VERSION 5.8 ;
BUSBITCHARS "[]" ;
DIVIDERCHAR "/" ;
UNITS
    DATABASE MICRONS 1000 ;
END UNITS

VIA ino_decode_queue_via1_2_1000_440_1_2_410_410
  VIARULE via1Array ;
  CUTSIZE 0.19 0.19 ;
  LAYERS Metal1 Via1 Metal2 ;
  CUTSPACING 0.22 0.22 ;
  ENCLOSURE 0.05 0.125 0.005 0.05 ;
  ROWCOL 1 2 ;
END ino_decode_queue_via1_2_1000_440_1_2_410_410

VIA ino_decode_queue_via2_3_1000_440_1_2_410_410
  VIARULE via2Array ;
  CUTSIZE 0.19 0.19 ;
  LAYERS Metal2 Via2 Metal3 ;
  CUTSPACING 0.22 0.22 ;
  ENCLOSURE 0.005 0.05 0.05 0.005 ;
  ROWCOL 1 2 ;
END ino_decode_queue_via2_3_1000_440_1_2_410_410

VIA ino_decode_queue_via3_4_1000_440_1_2_410_410
  VIARULE via3Array ;
  CUTSIZE 0.19 0.19 ;
  LAYERS Metal3 Via3 Metal4 ;
  CUTSPACING 0.22 0.22 ;
  ENCLOSURE 0.05 0.005 0.2 0.05 ;
  ROWCOL 1 2 ;
END ino_decode_queue_via3_4_1000_440_1_2_410_410

VIA ino_decode_queue_via4_5_1000_2000_1_1_840_840
  VIARULE viaTop1Array ;
  CUTSIZE 0.42 0.42 ;
  LAYERS Metal4 TopVia1 TopMetal1 ;
  CUTSPACING 0.42 0.42 ;
  ENCLOSURE 0.29 0.1 0.42 0.79 ;
END ino_decode_queue_via4_5_1000_2000_1_1_840_840

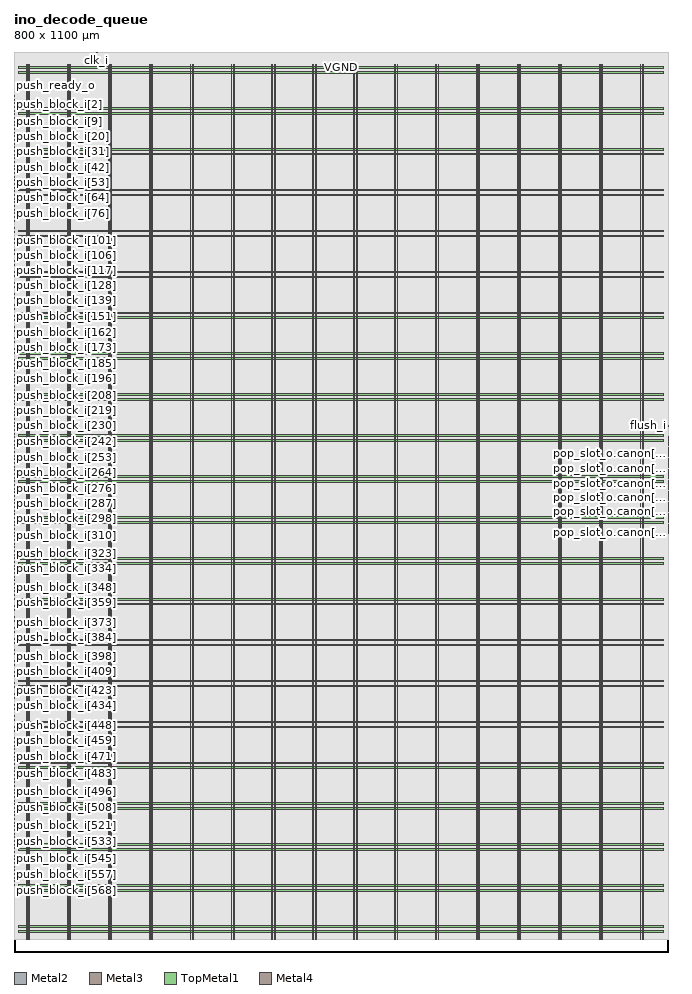
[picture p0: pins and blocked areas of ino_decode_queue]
MACRO ino_decode_queue
  FOREIGN ino_decode_queue 0 0 ;
  CLASS BLOCK ;
  SIZE 800 BY 1100 ;
  PIN clk_i
    DIRECTION INPUT ;
    USE SIGNAL ;
    PORT
      LAYER Metal2 ;
        RECT  101.08 1099.6 101.48 1100 ;
    END
  END clk_i
  PIN flush_i
    DIRECTION INPUT ;
    USE SIGNAL ;
    PORT
      LAYER Metal3 ;
        RECT  799.6 642.82 800 643.22 ;
    END
  END flush_i
  PIN pop_slot_o.canon[0]
    DIRECTION OUTPUT ;
    USE SIGNAL ;
    PORT
      LAYER Metal3 ;
        RECT  799.6 512.62 800 513.02 ;
    END
  END pop_slot_o.canon[0]
  PIN pop_slot_o.canon[10]
    DIRECTION OUTPUT ;
    USE SIGNAL ;
    PORT
      LAYER Metal3 ;
        RECT  799.6 537.82 800 538.22 ;
    END
  END pop_slot_o.canon[10]
  PIN pop_slot_o.canon[11]
    DIRECTION OUTPUT ;
    USE SIGNAL ;
    PORT
      LAYER Metal3 ;
        RECT  799.6 540.34 800 540.74 ;
    END
  END pop_slot_o.canon[11]
  PIN pop_slot_o.canon[12]
    DIRECTION OUTPUT ;
    USE SIGNAL ;
    PORT
      LAYER Metal3 ;
        RECT  799.6 542.86 800 543.26 ;
    END
  END pop_slot_o.canon[12]
  PIN pop_slot_o.canon[13]
    DIRECTION OUTPUT ;
    USE SIGNAL ;
    PORT
      LAYER Metal3 ;
        RECT  799.6 545.38 800 545.78 ;
    END
  END pop_slot_o.canon[13]
  PIN pop_slot_o.canon[14]
    DIRECTION OUTPUT ;
    USE SIGNAL ;
    PORT
      LAYER Metal3 ;
        RECT  799.6 547.9 800 548.3 ;
    END
  END pop_slot_o.canon[14]
  PIN pop_slot_o.canon[15]
    DIRECTION OUTPUT ;
    USE SIGNAL ;
    PORT
      LAYER Metal3 ;
        RECT  799.6 550.42 800 550.82 ;
    END
  END pop_slot_o.canon[15]
  PIN pop_slot_o.canon[16]
    DIRECTION OUTPUT ;
    USE SIGNAL ;
    PORT
      LAYER Metal3 ;
        RECT  799.6 552.94 800 553.34 ;
    END
  END pop_slot_o.canon[16]
  PIN pop_slot_o.canon[17]
    DIRECTION OUTPUT ;
    USE SIGNAL ;
    PORT
      LAYER Metal3 ;
        RECT  799.6 555.46 800 555.86 ;
    END
  END pop_slot_o.canon[17]
  PIN pop_slot_o.canon[18]
    DIRECTION OUTPUT ;
    USE SIGNAL ;
    PORT
      LAYER Metal3 ;
        RECT  799.6 557.98 800 558.38 ;
    END
  END pop_slot_o.canon[18]
  PIN pop_slot_o.canon[19]
    DIRECTION OUTPUT ;
    USE SIGNAL ;
    PORT
      LAYER Metal3 ;
        RECT  799.6 560.5 800 560.9 ;
    END
  END pop_slot_o.canon[19]
  PIN pop_slot_o.canon[1]
    DIRECTION OUTPUT ;
    USE SIGNAL ;
    PORT
      LAYER Metal3 ;
        RECT  799.6 515.14 800 515.54 ;
    END
  END pop_slot_o.canon[1]
  PIN pop_slot_o.canon[20]
    DIRECTION OUTPUT ;
    USE SIGNAL ;
    PORT
      LAYER Metal3 ;
        RECT  799.6 563.02 800 563.42 ;
    END
  END pop_slot_o.canon[20]
  PIN pop_slot_o.canon[21]
    DIRECTION OUTPUT ;
    USE SIGNAL ;
    PORT
      LAYER Metal3 ;
        RECT  799.6 565.54 800 565.94 ;
    END
  END pop_slot_o.canon[21]
  PIN pop_slot_o.canon[22]
    DIRECTION OUTPUT ;
    USE SIGNAL ;
    PORT
      LAYER Metal3 ;
        RECT  799.6 568.06 800 568.46 ;
    END
  END pop_slot_o.canon[22]
  PIN pop_slot_o.canon[23]
    DIRECTION OUTPUT ;
    USE SIGNAL ;
    PORT
      LAYER Metal3 ;
        RECT  799.6 570.58 800 570.98 ;
    END
  END pop_slot_o.canon[23]
  PIN pop_slot_o.canon[24]
    DIRECTION OUTPUT ;
    USE SIGNAL ;
    PORT
      LAYER Metal3 ;
        RECT  799.6 573.1 800 573.5 ;
    END
  END pop_slot_o.canon[24]
  PIN pop_slot_o.canon[25]
    DIRECTION OUTPUT ;
    USE SIGNAL ;
    PORT
      LAYER Metal3 ;
        RECT  799.6 575.62 800 576.02 ;
    END
  END pop_slot_o.canon[25]
  PIN pop_slot_o.canon[26]
    DIRECTION OUTPUT ;
    USE SIGNAL ;
    PORT
      LAYER Metal3 ;
        RECT  799.6 578.14 800 578.54 ;
    END
  END pop_slot_o.canon[26]
  PIN pop_slot_o.canon[27]
    DIRECTION OUTPUT ;
    USE SIGNAL ;
    PORT
      LAYER Metal3 ;
        RECT  799.6 580.66 800 581.06 ;
    END
  END pop_slot_o.canon[27]
  PIN pop_slot_o.canon[28]
    DIRECTION OUTPUT ;
    USE SIGNAL ;
    PORT
      LAYER Metal3 ;
        RECT  799.6 583.18 800 583.58 ;
    END
  END pop_slot_o.canon[28]
  PIN pop_slot_o.canon[29]
    DIRECTION OUTPUT ;
    USE SIGNAL ;
    PORT
      LAYER Metal3 ;
        RECT  799.6 585.7 800 586.1 ;
    END
  END pop_slot_o.canon[29]
  PIN pop_slot_o.canon[2]
    DIRECTION OUTPUT ;
    USE SIGNAL ;
    PORT
      LAYER Metal3 ;
        RECT  799.6 517.66 800 518.06 ;
    END
  END pop_slot_o.canon[2]
  PIN pop_slot_o.canon[30]
    DIRECTION OUTPUT ;
    USE SIGNAL ;
    PORT
      LAYER Metal3 ;
        RECT  799.6 588.22 800 588.62 ;
    END
  END pop_slot_o.canon[30]
  PIN pop_slot_o.canon[31]
    DIRECTION OUTPUT ;
    USE SIGNAL ;
    PORT
      LAYER Metal3 ;
        RECT  799.6 590.74 800 591.14 ;
    END
  END pop_slot_o.canon[31]
  PIN pop_slot_o.canon[32]
    DIRECTION OUTPUT ;
    USE SIGNAL ;
    PORT
      LAYER Metal3 ;
        RECT  799.6 593.26 800 593.66 ;
    END
  END pop_slot_o.canon[32]
  PIN pop_slot_o.canon[33]
    DIRECTION OUTPUT ;
    USE SIGNAL ;
    PORT
      LAYER Metal3 ;
        RECT  799.6 594.94 800 595.34 ;
    END
  END pop_slot_o.canon[33]
  PIN pop_slot_o.canon[34]
    DIRECTION OUTPUT ;
    USE SIGNAL ;
    PORT
      LAYER Metal3 ;
        RECT  799.6 596.62 800 597.02 ;
    END
  END pop_slot_o.canon[34]
  PIN pop_slot_o.canon[35]
    DIRECTION OUTPUT ;
    USE SIGNAL ;
    PORT
      LAYER Metal3 ;
        RECT  799.6 598.3 800 598.7 ;
    END
  END pop_slot_o.canon[35]
  PIN pop_slot_o.canon[36]
    DIRECTION OUTPUT ;
    USE SIGNAL ;
    PORT
      LAYER Metal3 ;
        RECT  799.6 599.98 800 600.38 ;
    END
  END pop_slot_o.canon[36]
  PIN pop_slot_o.canon[37]
    DIRECTION OUTPUT ;
    USE SIGNAL ;
    PORT
      LAYER Metal3 ;
        RECT  799.6 601.66 800 602.06 ;
    END
  END pop_slot_o.canon[37]
  PIN pop_slot_o.canon[38]
    DIRECTION OUTPUT ;
    USE SIGNAL ;
    PORT
      LAYER Metal3 ;
        RECT  799.6 603.34 800 603.74 ;
    END
  END pop_slot_o.canon[38]
  PIN pop_slot_o.canon[39]
    DIRECTION OUTPUT ;
    USE SIGNAL ;
    PORT
      LAYER Metal3 ;
        RECT  799.6 605.02 800 605.42 ;
    END
  END pop_slot_o.canon[39]
  PIN pop_slot_o.canon[3]
    DIRECTION OUTPUT ;
    USE SIGNAL ;
    PORT
      LAYER Metal3 ;
        RECT  799.6 520.18 800 520.58 ;
    END
  END pop_slot_o.canon[3]
  PIN pop_slot_o.canon[40]
    DIRECTION OUTPUT ;
    USE SIGNAL ;
    PORT
      LAYER Metal3 ;
        RECT  799.6 606.7 800 607.1 ;
    END
  END pop_slot_o.canon[40]
  PIN pop_slot_o.canon[41]
    DIRECTION OUTPUT ;
    USE SIGNAL ;
    PORT
      LAYER Metal3 ;
        RECT  799.6 608.38 800 608.78 ;
    END
  END pop_slot_o.canon[41]
  PIN pop_slot_o.canon[42]
    DIRECTION OUTPUT ;
    USE SIGNAL ;
    PORT
      LAYER Metal3 ;
        RECT  799.6 610.06 800 610.46 ;
    END
  END pop_slot_o.canon[42]
  PIN pop_slot_o.canon[43]
    DIRECTION OUTPUT ;
    USE SIGNAL ;
    PORT
      LAYER Metal3 ;
        RECT  799.6 611.74 800 612.14 ;
    END
  END pop_slot_o.canon[43]
  PIN pop_slot_o.canon[44]
    DIRECTION OUTPUT ;
    USE SIGNAL ;
    PORT
      LAYER Metal3 ;
        RECT  799.6 613.42 800 613.82 ;
    END
  END pop_slot_o.canon[44]
  PIN pop_slot_o.canon[45]
    DIRECTION OUTPUT ;
    USE SIGNAL ;
    PORT
      LAYER Metal3 ;
        RECT  799.6 615.1 800 615.5 ;
    END
  END pop_slot_o.canon[45]
  PIN pop_slot_o.canon[46]
    DIRECTION OUTPUT ;
    USE SIGNAL ;
    PORT
      LAYER Metal3 ;
        RECT  799.6 616.78 800 617.18 ;
    END
  END pop_slot_o.canon[46]
  PIN pop_slot_o.canon[47]
    DIRECTION OUTPUT ;
    USE SIGNAL ;
    PORT
      LAYER Metal3 ;
        RECT  799.6 618.46 800 618.86 ;
    END
  END pop_slot_o.canon[47]
  PIN pop_slot_o.canon[48]
    DIRECTION OUTPUT ;
    USE SIGNAL ;
    PORT
      LAYER Metal3 ;
        RECT  799.6 620.14 800 620.54 ;
    END
  END pop_slot_o.canon[48]
  PIN pop_slot_o.canon[49]
    DIRECTION OUTPUT ;
    USE SIGNAL ;
    PORT
      LAYER Metal3 ;
        RECT  799.6 621.82 800 622.22 ;
    END
  END pop_slot_o.canon[49]
  PIN pop_slot_o.canon[4]
    DIRECTION OUTPUT ;
    USE SIGNAL ;
    PORT
      LAYER Metal3 ;
        RECT  799.6 522.7 800 523.1 ;
    END
  END pop_slot_o.canon[4]
  PIN pop_slot_o.canon[50]
    DIRECTION OUTPUT ;
    USE SIGNAL ;
    PORT
      LAYER Metal3 ;
        RECT  799.6 623.5 800 623.9 ;
    END
  END pop_slot_o.canon[50]
  PIN pop_slot_o.canon[51]
    DIRECTION OUTPUT ;
    USE SIGNAL ;
    PORT
      LAYER Metal3 ;
        RECT  799.6 625.18 800 625.58 ;
    END
  END pop_slot_o.canon[51]
  PIN pop_slot_o.canon[52]
    DIRECTION OUTPUT ;
    USE SIGNAL ;
    PORT
      LAYER Metal3 ;
        RECT  799.6 626.86 800 627.26 ;
    END
  END pop_slot_o.canon[52]
  PIN pop_slot_o.canon[53]
    DIRECTION OUTPUT ;
    USE SIGNAL ;
    PORT
      LAYER Metal3 ;
        RECT  799.6 628.54 800 628.94 ;
    END
  END pop_slot_o.canon[53]
  PIN pop_slot_o.canon[54]
    DIRECTION OUTPUT ;
    USE SIGNAL ;
    PORT
      LAYER Metal3 ;
        RECT  799.6 630.22 800 630.62 ;
    END
  END pop_slot_o.canon[54]
  PIN pop_slot_o.canon[55]
    DIRECTION OUTPUT ;
    USE SIGNAL ;
    PORT
      LAYER Metal3 ;
        RECT  799.6 631.06 800 631.46 ;
    END
  END pop_slot_o.canon[55]
  PIN pop_slot_o.canon[5]
    DIRECTION OUTPUT ;
    USE SIGNAL ;
    PORT
      LAYER Metal3 ;
        RECT  799.6 525.22 800 525.62 ;
    END
  END pop_slot_o.canon[5]
  PIN pop_slot_o.canon[6]
    DIRECTION OUTPUT ;
    USE SIGNAL ;
    PORT
      LAYER Metal3 ;
        RECT  799.6 527.74 800 528.14 ;
    END
  END pop_slot_o.canon[6]
  PIN pop_slot_o.canon[7]
    DIRECTION OUTPUT ;
    USE SIGNAL ;
    PORT
      LAYER Metal3 ;
        RECT  799.6 530.26 800 530.66 ;
    END
  END pop_slot_o.canon[7]
  PIN pop_slot_o.canon[8]
    DIRECTION OUTPUT ;
    USE SIGNAL ;
    PORT
      LAYER Metal3 ;
        RECT  799.6 532.78 800 533.18 ;
    END
  END pop_slot_o.canon[8]
  PIN pop_slot_o.canon[9]
    DIRECTION OUTPUT ;
    USE SIGNAL ;
    PORT
      LAYER Metal3 ;
        RECT  799.6 535.3 800 535.7 ;
    END
  END pop_slot_o.canon[9]
  PIN pop_slot_o.pc[0]
    DIRECTION OUTPUT ;
    USE SIGNAL ;
    PORT
      LAYER Metal3 ;
        RECT  799.6 513.46 800 513.86 ;
    END
  END pop_slot_o.pc[0]
  PIN pop_slot_o.pc[10]
    DIRECTION OUTPUT ;
    USE SIGNAL ;
    PORT
      LAYER Metal3 ;
        RECT  799.6 538.66 800 539.06 ;
    END
  END pop_slot_o.pc[10]
  PIN pop_slot_o.pc[11]
    DIRECTION OUTPUT ;
    USE SIGNAL ;
    PORT
      LAYER Metal3 ;
        RECT  799.6 541.18 800 541.58 ;
    END
  END pop_slot_o.pc[11]
  PIN pop_slot_o.pc[12]
    DIRECTION OUTPUT ;
    USE SIGNAL ;
    PORT
      LAYER Metal3 ;
        RECT  799.6 543.7 800 544.1 ;
    END
  END pop_slot_o.pc[12]
  PIN pop_slot_o.pc[13]
    DIRECTION OUTPUT ;
    USE SIGNAL ;
    PORT
      LAYER Metal3 ;
        RECT  799.6 546.22 800 546.62 ;
    END
  END pop_slot_o.pc[13]
  PIN pop_slot_o.pc[14]
    DIRECTION OUTPUT ;
    USE SIGNAL ;
    PORT
      LAYER Metal3 ;
        RECT  799.6 548.74 800 549.14 ;
    END
  END pop_slot_o.pc[14]
  PIN pop_slot_o.pc[15]
    DIRECTION OUTPUT ;
    USE SIGNAL ;
    PORT
      LAYER Metal3 ;
        RECT  799.6 551.26 800 551.66 ;
    END
  END pop_slot_o.pc[15]
  PIN pop_slot_o.pc[16]
    DIRECTION OUTPUT ;
    USE SIGNAL ;
    PORT
      LAYER Metal3 ;
        RECT  799.6 553.78 800 554.18 ;
    END
  END pop_slot_o.pc[16]
  PIN pop_slot_o.pc[17]
    DIRECTION OUTPUT ;
    USE SIGNAL ;
    PORT
      LAYER Metal3 ;
        RECT  799.6 556.3 800 556.7 ;
    END
  END pop_slot_o.pc[17]
  PIN pop_slot_o.pc[18]
    DIRECTION OUTPUT ;
    USE SIGNAL ;
    PORT
      LAYER Metal3 ;
        RECT  799.6 558.82 800 559.22 ;
    END
  END pop_slot_o.pc[18]
  PIN pop_slot_o.pc[19]
    DIRECTION OUTPUT ;
    USE SIGNAL ;
    PORT
      LAYER Metal3 ;
        RECT  799.6 561.34 800 561.74 ;
    END
  END pop_slot_o.pc[19]
  PIN pop_slot_o.pc[1]
    DIRECTION OUTPUT ;
    USE SIGNAL ;
    PORT
      LAYER Metal3 ;
        RECT  799.6 515.98 800 516.38 ;
    END
  END pop_slot_o.pc[1]
  PIN pop_slot_o.pc[20]
    DIRECTION OUTPUT ;
    USE SIGNAL ;
    PORT
      LAYER Metal3 ;
        RECT  799.6 563.86 800 564.26 ;
    END
  END pop_slot_o.pc[20]
  PIN pop_slot_o.pc[21]
    DIRECTION OUTPUT ;
    USE SIGNAL ;
    PORT
      LAYER Metal3 ;
        RECT  799.6 566.38 800 566.78 ;
    END
  END pop_slot_o.pc[21]
  PIN pop_slot_o.pc[22]
    DIRECTION OUTPUT ;
    USE SIGNAL ;
    PORT
      LAYER Metal3 ;
        RECT  799.6 568.9 800 569.3 ;
    END
  END pop_slot_o.pc[22]
  PIN pop_slot_o.pc[23]
    DIRECTION OUTPUT ;
    USE SIGNAL ;
    PORT
      LAYER Metal3 ;
        RECT  799.6 571.42 800 571.82 ;
    END
  END pop_slot_o.pc[23]
  PIN pop_slot_o.pc[24]
    DIRECTION OUTPUT ;
    USE SIGNAL ;
    PORT
      LAYER Metal3 ;
        RECT  799.6 573.94 800 574.34 ;
    END
  END pop_slot_o.pc[24]
  PIN pop_slot_o.pc[25]
    DIRECTION OUTPUT ;
    USE SIGNAL ;
    PORT
      LAYER Metal3 ;
        RECT  799.6 576.46 800 576.86 ;
    END
  END pop_slot_o.pc[25]
  PIN pop_slot_o.pc[26]
    DIRECTION OUTPUT ;
    USE SIGNAL ;
    PORT
      LAYER Metal3 ;
        RECT  799.6 578.98 800 579.38 ;
    END
  END pop_slot_o.pc[26]
  PIN pop_slot_o.pc[27]
    DIRECTION OUTPUT ;
    USE SIGNAL ;
    PORT
      LAYER Metal3 ;
        RECT  799.6 581.5 800 581.9 ;
    END
  END pop_slot_o.pc[27]
  PIN pop_slot_o.pc[28]
    DIRECTION OUTPUT ;
    USE SIGNAL ;
    PORT
      LAYER Metal3 ;
        RECT  799.6 584.02 800 584.42 ;
    END
  END pop_slot_o.pc[28]
  PIN pop_slot_o.pc[29]
    DIRECTION OUTPUT ;
    USE SIGNAL ;
    PORT
      LAYER Metal3 ;
        RECT  799.6 586.54 800 586.94 ;
    END
  END pop_slot_o.pc[29]
  PIN pop_slot_o.pc[2]
    DIRECTION OUTPUT ;
    USE SIGNAL ;
    PORT
      LAYER Metal3 ;
        RECT  799.6 518.5 800 518.9 ;
    END
  END pop_slot_o.pc[2]
  PIN pop_slot_o.pc[30]
    DIRECTION OUTPUT ;
    USE SIGNAL ;
    PORT
      LAYER Metal3 ;
        RECT  799.6 589.06 800 589.46 ;
    END
  END pop_slot_o.pc[30]
  PIN pop_slot_o.pc[31]
    DIRECTION OUTPUT ;
    USE SIGNAL ;
    PORT
      LAYER Metal3 ;
        RECT  799.6 591.58 800 591.98 ;
    END
  END pop_slot_o.pc[31]
  PIN pop_slot_o.pc[3]
    DIRECTION OUTPUT ;
    USE SIGNAL ;
    PORT
      LAYER Metal3 ;
        RECT  799.6 521.02 800 521.42 ;
    END
  END pop_slot_o.pc[3]
  PIN pop_slot_o.pc[4]
    DIRECTION OUTPUT ;
    USE SIGNAL ;
    PORT
      LAYER Metal3 ;
        RECT  799.6 523.54 800 523.94 ;
    END
  END pop_slot_o.pc[4]
  PIN pop_slot_o.pc[5]
    DIRECTION OUTPUT ;
    USE SIGNAL ;
    PORT
      LAYER Metal3 ;
        RECT  799.6 526.06 800 526.46 ;
    END
  END pop_slot_o.pc[5]
  PIN pop_slot_o.pc[6]
    DIRECTION OUTPUT ;
    USE SIGNAL ;
    PORT
      LAYER Metal3 ;
        RECT  799.6 528.58 800 528.98 ;
    END
  END pop_slot_o.pc[6]
  PIN pop_slot_o.pc[7]
    DIRECTION OUTPUT ;
    USE SIGNAL ;
    PORT
      LAYER Metal3 ;
        RECT  799.6 531.1 800 531.5 ;
    END
  END pop_slot_o.pc[7]
  PIN pop_slot_o.pc[8]
    DIRECTION OUTPUT ;
    USE SIGNAL ;
    PORT
      LAYER Metal3 ;
        RECT  799.6 533.62 800 534.02 ;
    END
  END pop_slot_o.pc[8]
  PIN pop_slot_o.pc[9]
    DIRECTION OUTPUT ;
    USE SIGNAL ;
    PORT
      LAYER Metal3 ;
        RECT  799.6 536.14 800 536.54 ;
    END
  END pop_slot_o.pc[9]
  PIN pop_slot_o.pred[0]
    DIRECTION OUTPUT ;
    USE SIGNAL ;
    PORT
      LAYER Metal3 ;
        RECT  799.6 514.3 800 514.7 ;
    END
  END pop_slot_o.pred[0]
  PIN pop_slot_o.pred[10]
    DIRECTION OUTPUT ;
    USE SIGNAL ;
    PORT
      LAYER Metal3 ;
        RECT  799.6 539.5 800 539.9 ;
    END
  END pop_slot_o.pred[10]
  PIN pop_slot_o.pred[11]
    DIRECTION OUTPUT ;
    USE SIGNAL ;
    PORT
      LAYER Metal3 ;
        RECT  799.6 542.02 800 542.42 ;
    END
  END pop_slot_o.pred[11]
  PIN pop_slot_o.pred[12]
    DIRECTION OUTPUT ;
    USE SIGNAL ;
    PORT
      LAYER Metal3 ;
        RECT  799.6 544.54 800 544.94 ;
    END
  END pop_slot_o.pred[12]
  PIN pop_slot_o.pred[13]
    DIRECTION OUTPUT ;
    USE SIGNAL ;
    PORT
      LAYER Metal3 ;
        RECT  799.6 547.06 800 547.46 ;
    END
  END pop_slot_o.pred[13]
  PIN pop_slot_o.pred[14]
    DIRECTION OUTPUT ;
    USE SIGNAL ;
    PORT
      LAYER Metal3 ;
        RECT  799.6 549.58 800 549.98 ;
    END
  END pop_slot_o.pred[14]
  PIN pop_slot_o.pred[15]
    DIRECTION OUTPUT ;
    USE SIGNAL ;
    PORT
      LAYER Metal3 ;
        RECT  799.6 552.1 800 552.5 ;
    END
  END pop_slot_o.pred[15]
  PIN pop_slot_o.pred[16]
    DIRECTION OUTPUT ;
    USE SIGNAL ;
    PORT
      LAYER Metal3 ;
        RECT  799.6 554.62 800 555.02 ;
    END
  END pop_slot_o.pred[16]
  PIN pop_slot_o.pred[17]
    DIRECTION OUTPUT ;
    USE SIGNAL ;
    PORT
      LAYER Metal3 ;
        RECT  799.6 557.14 800 557.54 ;
    END
  END pop_slot_o.pred[17]
  PIN pop_slot_o.pred[18]
    DIRECTION OUTPUT ;
    USE SIGNAL ;
    PORT
      LAYER Metal3 ;
        RECT  799.6 559.66 800 560.06 ;
    END
  END pop_slot_o.pred[18]
  PIN pop_slot_o.pred[19]
    DIRECTION OUTPUT ;
    USE SIGNAL ;
    PORT
      LAYER Metal3 ;
        RECT  799.6 562.18 800 562.58 ;
    END
  END pop_slot_o.pred[19]
  PIN pop_slot_o.pred[1]
    DIRECTION OUTPUT ;
    USE SIGNAL ;
    PORT
      LAYER Metal3 ;
        RECT  799.6 516.82 800 517.22 ;
    END
  END pop_slot_o.pred[1]
  PIN pop_slot_o.pred[20]
    DIRECTION OUTPUT ;
    USE SIGNAL ;
    PORT
      LAYER Metal3 ;
        RECT  799.6 564.7 800 565.1 ;
    END
  END pop_slot_o.pred[20]
  PIN pop_slot_o.pred[21]
    DIRECTION OUTPUT ;
    USE SIGNAL ;
    PORT
      LAYER Metal3 ;
        RECT  799.6 567.22 800 567.62 ;
    END
  END pop_slot_o.pred[21]
  PIN pop_slot_o.pred[22]
    DIRECTION OUTPUT ;
    USE SIGNAL ;
    PORT
      LAYER Metal3 ;
        RECT  799.6 569.74 800 570.14 ;
    END
  END pop_slot_o.pred[22]
  PIN pop_slot_o.pred[23]
    DIRECTION OUTPUT ;
    USE SIGNAL ;
    PORT
      LAYER Metal3 ;
        RECT  799.6 572.26 800 572.66 ;
    END
  END pop_slot_o.pred[23]
  PIN pop_slot_o.pred[24]
    DIRECTION OUTPUT ;
    USE SIGNAL ;
    PORT
      LAYER Metal3 ;
        RECT  799.6 574.78 800 575.18 ;
    END
  END pop_slot_o.pred[24]
  PIN pop_slot_o.pred[25]
    DIRECTION OUTPUT ;
    USE SIGNAL ;
    PORT
      LAYER Metal3 ;
        RECT  799.6 577.3 800 577.7 ;
    END
  END pop_slot_o.pred[25]
  PIN pop_slot_o.pred[26]
    DIRECTION OUTPUT ;
    USE SIGNAL ;
    PORT
      LAYER Metal3 ;
        RECT  799.6 579.82 800 580.22 ;
    END
  END pop_slot_o.pred[26]
  PIN pop_slot_o.pred[27]
    DIRECTION OUTPUT ;
    USE SIGNAL ;
    PORT
      LAYER Metal3 ;
        RECT  799.6 582.34 800 582.74 ;
    END
  END pop_slot_o.pred[27]
  PIN pop_slot_o.pred[28]
    DIRECTION OUTPUT ;
    USE SIGNAL ;
    PORT
      LAYER Metal3 ;
        RECT  799.6 584.86 800 585.26 ;
    END
  END pop_slot_o.pred[28]
  PIN pop_slot_o.pred[29]
    DIRECTION OUTPUT ;
    USE SIGNAL ;
    PORT
      LAYER Metal3 ;
        RECT  799.6 587.38 800 587.78 ;
    END
  END pop_slot_o.pred[29]
  PIN pop_slot_o.pred[2]
    DIRECTION OUTPUT ;
    USE SIGNAL ;
    PORT
      LAYER Metal3 ;
        RECT  799.6 519.34 800 519.74 ;
    END
  END pop_slot_o.pred[2]
  PIN pop_slot_o.pred[30]
    DIRECTION OUTPUT ;
    USE SIGNAL ;
    PORT
      LAYER Metal3 ;
        RECT  799.6 589.9 800 590.3 ;
    END
  END pop_slot_o.pred[30]
  PIN pop_slot_o.pred[31]
    DIRECTION OUTPUT ;
    USE SIGNAL ;
    PORT
      LAYER Metal3 ;
        RECT  799.6 592.42 800 592.82 ;
    END
  END pop_slot_o.pred[31]
  PIN pop_slot_o.pred[32]
    DIRECTION OUTPUT ;
    USE SIGNAL ;
    PORT
      LAYER Metal3 ;
        RECT  799.6 594.1 800 594.5 ;
    END
  END pop_slot_o.pred[32]
  PIN pop_slot_o.pred[33]
    DIRECTION OUTPUT ;
    USE SIGNAL ;
    PORT
      LAYER Metal3 ;
        RECT  799.6 595.78 800 596.18 ;
    END
  END pop_slot_o.pred[33]
  PIN pop_slot_o.pred[34]
    DIRECTION OUTPUT ;
    USE SIGNAL ;
    PORT
      LAYER Metal3 ;
        RECT  799.6 597.46 800 597.86 ;
    END
  END pop_slot_o.pred[34]
  PIN pop_slot_o.pred[35]
    DIRECTION OUTPUT ;
    USE SIGNAL ;
    PORT
      LAYER Metal3 ;
        RECT  799.6 599.14 800 599.54 ;
    END
  END pop_slot_o.pred[35]
  PIN pop_slot_o.pred[36]
    DIRECTION OUTPUT ;
    USE SIGNAL ;
    PORT
      LAYER Metal3 ;
        RECT  799.6 600.82 800 601.22 ;
    END
  END pop_slot_o.pred[36]
  PIN pop_slot_o.pred[37]
    DIRECTION OUTPUT ;
    USE SIGNAL ;
    PORT
      LAYER Metal3 ;
        RECT  799.6 602.5 800 602.9 ;
    END
  END pop_slot_o.pred[37]
  PIN pop_slot_o.pred[38]
    DIRECTION OUTPUT ;
    USE SIGNAL ;
    PORT
      LAYER Metal3 ;
        RECT  799.6 604.18 800 604.58 ;
    END
  END pop_slot_o.pred[38]
  PIN pop_slot_o.pred[39]
    DIRECTION OUTPUT ;
    USE SIGNAL ;
    PORT
      LAYER Metal3 ;
        RECT  799.6 605.86 800 606.26 ;
    END
  END pop_slot_o.pred[39]
  PIN pop_slot_o.pred[3]
    DIRECTION OUTPUT ;
    USE SIGNAL ;
    PORT
      LAYER Metal3 ;
        RECT  799.6 521.86 800 522.26 ;
    END
  END pop_slot_o.pred[3]
  PIN pop_slot_o.pred[40]
    DIRECTION OUTPUT ;
    USE SIGNAL ;
    PORT
      LAYER Metal3 ;
        RECT  799.6 607.54 800 607.94 ;
    END
  END pop_slot_o.pred[40]
  PIN pop_slot_o.pred[41]
    DIRECTION OUTPUT ;
    USE SIGNAL ;
    PORT
      LAYER Metal3 ;
        RECT  799.6 609.22 800 609.62 ;
    END
  END pop_slot_o.pred[41]
  PIN pop_slot_o.pred[42]
    DIRECTION OUTPUT ;
    USE SIGNAL ;
    PORT
      LAYER Metal3 ;
        RECT  799.6 610.9 800 611.3 ;
    END
  END pop_slot_o.pred[42]
  PIN pop_slot_o.pred[43]
    DIRECTION OUTPUT ;
    USE SIGNAL ;
    PORT
      LAYER Metal3 ;
        RECT  799.6 612.58 800 612.98 ;
    END
  END pop_slot_o.pred[43]
  PIN pop_slot_o.pred[44]
    DIRECTION OUTPUT ;
    USE SIGNAL ;
    PORT
      LAYER Metal3 ;
        RECT  799.6 614.26 800 614.66 ;
    END
  END pop_slot_o.pred[44]
  PIN pop_slot_o.pred[45]
    DIRECTION OUTPUT ;
    USE SIGNAL ;
    PORT
      LAYER Metal3 ;
        RECT  799.6 615.94 800 616.34 ;
    END
  END pop_slot_o.pred[45]
  PIN pop_slot_o.pred[46]
    DIRECTION OUTPUT ;
    USE SIGNAL ;
    PORT
      LAYER Metal3 ;
        RECT  799.6 617.62 800 618.02 ;
    END
  END pop_slot_o.pred[46]
  PIN pop_slot_o.pred[47]
    DIRECTION OUTPUT ;
    USE SIGNAL ;
    PORT
      LAYER Metal3 ;
        RECT  799.6 619.3 800 619.7 ;
    END
  END pop_slot_o.pred[47]
  PIN pop_slot_o.pred[48]
    DIRECTION OUTPUT ;
    USE SIGNAL ;
    PORT
      LAYER Metal3 ;
        RECT  799.6 620.98 800 621.38 ;
    END
  END pop_slot_o.pred[48]
  PIN pop_slot_o.pred[49]
    DIRECTION OUTPUT ;
    USE SIGNAL ;
    PORT
      LAYER Metal3 ;
        RECT  799.6 622.66 800 623.06 ;
    END
  END pop_slot_o.pred[49]
  PIN pop_slot_o.pred[4]
    DIRECTION OUTPUT ;
    USE SIGNAL ;
    PORT
      LAYER Metal3 ;
        RECT  799.6 524.38 800 524.78 ;
    END
  END pop_slot_o.pred[4]
  PIN pop_slot_o.pred[50]
    DIRECTION OUTPUT ;
    USE SIGNAL ;
    PORT
      LAYER Metal3 ;
        RECT  799.6 624.34 800 624.74 ;
    END
  END pop_slot_o.pred[50]
  PIN pop_slot_o.pred[51]
    DIRECTION OUTPUT ;
    USE SIGNAL ;
    PORT
      LAYER Metal3 ;
        RECT  799.6 626.02 800 626.42 ;
    END
  END pop_slot_o.pred[51]
  PIN pop_slot_o.pred[52]
    DIRECTION OUTPUT ;
    USE SIGNAL ;
    PORT
      LAYER Metal3 ;
        RECT  799.6 627.7 800 628.1 ;
    END
  END pop_slot_o.pred[52]
  PIN pop_slot_o.pred[53]
    DIRECTION OUTPUT ;
    USE SIGNAL ;
    PORT
      LAYER Metal3 ;
        RECT  799.6 629.38 800 629.78 ;
    END
  END pop_slot_o.pred[53]
  PIN pop_slot_o.pred[5]
    DIRECTION OUTPUT ;
    USE SIGNAL ;
    PORT
      LAYER Metal3 ;
        RECT  799.6 526.9 800 527.3 ;
    END
  END pop_slot_o.pred[5]
  PIN pop_slot_o.pred[6]
    DIRECTION OUTPUT ;
    USE SIGNAL ;
    PORT
      LAYER Metal3 ;
        RECT  799.6 529.42 800 529.82 ;
    END
  END pop_slot_o.pred[6]
  PIN pop_slot_o.pred[7]
    DIRECTION OUTPUT ;
    USE SIGNAL ;
    PORT
      LAYER Metal3 ;
        RECT  799.6 531.94 800 532.34 ;
    END
  END pop_slot_o.pred[7]
  PIN pop_slot_o.pred[8]
    DIRECTION OUTPUT ;
    USE SIGNAL ;
    PORT
      LAYER Metal3 ;
        RECT  799.6 534.46 800 534.86 ;
    END
  END pop_slot_o.pred[8]
  PIN pop_slot_o.pred[9]
    DIRECTION OUTPUT ;
    USE SIGNAL ;
    PORT
      LAYER Metal3 ;
        RECT  799.6 536.98 800 537.38 ;
    END
  END pop_slot_o.pred[9]
  PIN pop_slot_o.valid
    DIRECTION OUTPUT ;
    USE SIGNAL ;
    PORT
      LAYER Metal3 ;
        RECT  799.6 511.78 800 512.18 ;
    END
  END pop_slot_o.valid
  PIN pop_take_i
    DIRECTION INPUT ;
    USE SIGNAL ;
    PORT
      LAYER Metal3 ;
        RECT  799.6 636.94 800 637.34 ;
    END
  END pop_take_i
  PIN push_block_i[0]
    DIRECTION INPUT ;
    USE SIGNAL ;
    PORT
      LAYER Metal3 ;
        RECT  0 1039.3 0.4 1039.7 ;
    END
  END push_block_i[0]
  PIN push_block_i[100]
    DIRECTION INPUT ;
    USE SIGNAL ;
    PORT
      LAYER Metal3 ;
        RECT  0 871.3 0.4 871.7 ;
    END
  END push_block_i[100]
  PIN push_block_i[101]
    DIRECTION INPUT ;
    USE SIGNAL ;
    PORT
      LAYER Metal3 ;
        RECT  0 869.62 0.4 870.02 ;
    END
  END push_block_i[101]
  PIN push_block_i[102]
    DIRECTION INPUT ;
    USE SIGNAL ;
    PORT
      LAYER Metal3 ;
        RECT  0 867.94 0.4 868.34 ;
    END
  END push_block_i[102]
  PIN push_block_i[103]
    DIRECTION INPUT ;
    USE SIGNAL ;
    PORT
      LAYER Metal3 ;
        RECT  0 866.26 0.4 866.66 ;
    END
  END push_block_i[103]
  PIN push_block_i[104]
    DIRECTION INPUT ;
    USE SIGNAL ;
    PORT
      LAYER Metal3 ;
        RECT  0 864.58 0.4 864.98 ;
    END
  END push_block_i[104]
  PIN push_block_i[105]
    DIRECTION INPUT ;
    USE SIGNAL ;
    PORT
      LAYER Metal3 ;
        RECT  0 862.9 0.4 863.3 ;
    END
  END push_block_i[105]
  PIN push_block_i[106]
    DIRECTION INPUT ;
    USE SIGNAL ;
    PORT
      LAYER Metal3 ;
        RECT  0 861.22 0.4 861.62 ;
    END
  END push_block_i[106]
  PIN push_block_i[107]
    DIRECTION INPUT ;
    USE SIGNAL ;
    PORT
      LAYER Metal3 ;
        RECT  0 859.54 0.4 859.94 ;
    END
  END push_block_i[107]
  PIN push_block_i[108]
    DIRECTION INPUT ;
    USE SIGNAL ;
    PORT
      LAYER Metal3 ;
        RECT  0 857.86 0.4 858.26 ;
    END
  END push_block_i[108]
  PIN push_block_i[109]
    DIRECTION INPUT ;
    USE SIGNAL ;
    PORT
      LAYER Metal3 ;
        RECT  0 856.18 0.4 856.58 ;
    END
  END push_block_i[109]
  PIN push_block_i[10]
    DIRECTION INPUT ;
    USE SIGNAL ;
    PORT
      LAYER Metal3 ;
        RECT  0 1022.5 0.4 1022.9 ;
    END
  END push_block_i[10]
  PIN push_block_i[110]
    DIRECTION INPUT ;
    USE SIGNAL ;
    PORT
      LAYER Metal3 ;
        RECT  0 854.5 0.4 854.9 ;
    END
  END push_block_i[110]
  PIN push_block_i[111]
    DIRECTION INPUT ;
    USE SIGNAL ;
    PORT
      LAYER Metal3 ;
        RECT  0 852.82 0.4 853.22 ;
    END
  END push_block_i[111]
  PIN push_block_i[112]
    DIRECTION INPUT ;
    USE SIGNAL ;
    PORT
      LAYER Metal3 ;
        RECT  0 851.14 0.4 851.54 ;
    END
  END push_block_i[112]
  PIN push_block_i[113]
    DIRECTION INPUT ;
    USE SIGNAL ;
    PORT
      LAYER Metal3 ;
        RECT  0 849.46 0.4 849.86 ;
    END
  END push_block_i[113]
  PIN push_block_i[114]
    DIRECTION INPUT ;
    USE SIGNAL ;
    PORT
      LAYER Metal3 ;
        RECT  0 847.78 0.4 848.18 ;
    END
  END push_block_i[114]
  PIN push_block_i[115]
    DIRECTION INPUT ;
    USE SIGNAL ;
    PORT
      LAYER Metal3 ;
        RECT  0 846.1 0.4 846.5 ;
    END
  END push_block_i[115]
  PIN push_block_i[116]
    DIRECTION INPUT ;
    USE SIGNAL ;
    PORT
      LAYER Metal3 ;
        RECT  0 844.42 0.4 844.82 ;
    END
  END push_block_i[116]
  PIN push_block_i[117]
    DIRECTION INPUT ;
    USE SIGNAL ;
    PORT
      LAYER Metal3 ;
        RECT  0 842.74 0.4 843.14 ;
    END
  END push_block_i[117]
  PIN push_block_i[118]
    DIRECTION INPUT ;
    USE SIGNAL ;
    PORT
      LAYER Metal3 ;
        RECT  0 841.06 0.4 841.46 ;
    END
  END push_block_i[118]
  PIN push_block_i[119]
    DIRECTION INPUT ;
    USE SIGNAL ;
    PORT
      LAYER Metal3 ;
        RECT  0 839.38 0.4 839.78 ;
    END
  END push_block_i[119]
  PIN push_block_i[11]
    DIRECTION INPUT ;
    USE SIGNAL ;
    PORT
      LAYER Metal3 ;
        RECT  0 1020.82 0.4 1021.22 ;
    END
  END push_block_i[11]
  PIN push_block_i[120]
    DIRECTION INPUT ;
    USE SIGNAL ;
    PORT
      LAYER Metal3 ;
        RECT  0 837.7 0.4 838.1 ;
    END
  END push_block_i[120]
  PIN push_block_i[121]
    DIRECTION INPUT ;
    USE SIGNAL ;
    PORT
      LAYER Metal3 ;
        RECT  0 836.02 0.4 836.42 ;
    END
  END push_block_i[121]
  PIN push_block_i[122]
    DIRECTION INPUT ;
    USE SIGNAL ;
    PORT
      LAYER Metal3 ;
        RECT  0 834.34 0.4 834.74 ;
    END
  END push_block_i[122]
  PIN push_block_i[123]
    DIRECTION INPUT ;
    USE SIGNAL ;
    PORT
      LAYER Metal3 ;
        RECT  0 832.66 0.4 833.06 ;
    END
  END push_block_i[123]
  PIN push_block_i[124]
    DIRECTION INPUT ;
    USE SIGNAL ;
    PORT
      LAYER Metal3 ;
        RECT  0 830.98 0.4 831.38 ;
    END
  END push_block_i[124]
  PIN push_block_i[125]
    DIRECTION INPUT ;
    USE SIGNAL ;
    PORT
      LAYER Metal3 ;
        RECT  0 829.3 0.4 829.7 ;
    END
  END push_block_i[125]
  PIN push_block_i[126]
    DIRECTION INPUT ;
    USE SIGNAL ;
    PORT
      LAYER Metal3 ;
        RECT  0 827.62 0.4 828.02 ;
    END
  END push_block_i[126]
  PIN push_block_i[127]
    DIRECTION INPUT ;
    USE SIGNAL ;
    PORT
      LAYER Metal3 ;
        RECT  0 825.94 0.4 826.34 ;
    END
  END push_block_i[127]
  PIN push_block_i[128]
    DIRECTION INPUT ;
    USE SIGNAL ;
    PORT
      LAYER Metal3 ;
        RECT  0 824.26 0.4 824.66 ;
    END
  END push_block_i[128]
  PIN push_block_i[129]
    DIRECTION INPUT ;
    USE SIGNAL ;
    PORT
      LAYER Metal3 ;
        RECT  0 822.58 0.4 822.98 ;
    END
  END push_block_i[129]
  PIN push_block_i[12]
    DIRECTION INPUT ;
    USE SIGNAL ;
    PORT
      LAYER Metal3 ;
        RECT  0 1019.14 0.4 1019.54 ;
    END
  END push_block_i[12]
  PIN push_block_i[130]
    DIRECTION INPUT ;
    USE SIGNAL ;
    PORT
      LAYER Metal3 ;
        RECT  0 820.9 0.4 821.3 ;
    END
  END push_block_i[130]
  PIN push_block_i[131]
    DIRECTION INPUT ;
    USE SIGNAL ;
    PORT
      LAYER Metal3 ;
        RECT  0 819.22 0.4 819.62 ;
    END
  END push_block_i[131]
  PIN push_block_i[132]
    DIRECTION INPUT ;
    USE SIGNAL ;
    PORT
      LAYER Metal3 ;
        RECT  0 817.54 0.4 817.94 ;
    END
  END push_block_i[132]
  PIN push_block_i[133]
    DIRECTION INPUT ;
    USE SIGNAL ;
    PORT
      LAYER Metal3 ;
        RECT  0 815.86 0.4 816.26 ;
    END
  END push_block_i[133]
  PIN push_block_i[134]
    DIRECTION INPUT ;
    USE SIGNAL ;
    PORT
      LAYER Metal3 ;
        RECT  0 814.18 0.4 814.58 ;
    END
  END push_block_i[134]
  PIN push_block_i[135]
    DIRECTION INPUT ;
    USE SIGNAL ;
    PORT
      LAYER Metal3 ;
        RECT  0 812.5 0.4 812.9 ;
    END
  END push_block_i[135]
  PIN push_block_i[136]
    DIRECTION INPUT ;
    USE SIGNAL ;
    PORT
      LAYER Metal3 ;
        RECT  0 810.82 0.4 811.22 ;
    END
  END push_block_i[136]
  PIN push_block_i[137]
    DIRECTION INPUT ;
    USE SIGNAL ;
    PORT
      LAYER Metal3 ;
        RECT  0 809.14 0.4 809.54 ;
    END
  END push_block_i[137]
  PIN push_block_i[138]
    DIRECTION INPUT ;
    USE SIGNAL ;
    PORT
      LAYER Metal3 ;
        RECT  0 807.46 0.4 807.86 ;
    END
  END push_block_i[138]
  PIN push_block_i[139]
    DIRECTION INPUT ;
    USE SIGNAL ;
    PORT
      LAYER Metal3 ;
        RECT  0 805.78 0.4 806.18 ;
    END
  END push_block_i[139]
  PIN push_block_i[13]
    DIRECTION INPUT ;
    USE SIGNAL ;
    PORT
      LAYER Metal3 ;
        RECT  0 1017.46 0.4 1017.86 ;
    END
  END push_block_i[13]
  PIN push_block_i[140]
    DIRECTION INPUT ;
    USE SIGNAL ;
    PORT
      LAYER Metal3 ;
        RECT  0 804.1 0.4 804.5 ;
    END
  END push_block_i[140]
  PIN push_block_i[141]
    DIRECTION INPUT ;
    USE SIGNAL ;
    PORT
      LAYER Metal3 ;
        RECT  0 802.42 0.4 802.82 ;
    END
  END push_block_i[141]
  PIN push_block_i[142]
    DIRECTION INPUT ;
    USE SIGNAL ;
    PORT
      LAYER Metal3 ;
        RECT  0 800.74 0.4 801.14 ;
    END
  END push_block_i[142]
  PIN push_block_i[143]
    DIRECTION INPUT ;
    USE SIGNAL ;
    PORT
      LAYER Metal3 ;
        RECT  0 799.06 0.4 799.46 ;
    END
  END push_block_i[143]
  PIN push_block_i[144]
    DIRECTION INPUT ;
    USE SIGNAL ;
    PORT
      LAYER Metal3 ;
        RECT  0 797.38 0.4 797.78 ;
    END
  END push_block_i[144]
  PIN push_block_i[145]
    DIRECTION INPUT ;
    USE SIGNAL ;
    PORT
      LAYER Metal3 ;
        RECT  0 795.7 0.4 796.1 ;
    END
  END push_block_i[145]
  PIN push_block_i[146]
    DIRECTION INPUT ;
    USE SIGNAL ;
    PORT
      LAYER Metal3 ;
        RECT  0 794.02 0.4 794.42 ;
    END
  END push_block_i[146]
  PIN push_block_i[147]
    DIRECTION INPUT ;
    USE SIGNAL ;
    PORT
      LAYER Metal3 ;
        RECT  0 792.34 0.4 792.74 ;
    END
  END push_block_i[147]
  PIN push_block_i[148]
    DIRECTION INPUT ;
    USE SIGNAL ;
    PORT
      LAYER Metal3 ;
        RECT  0 790.66 0.4 791.06 ;
    END
  END push_block_i[148]
  PIN push_block_i[149]
    DIRECTION INPUT ;
    USE SIGNAL ;
    PORT
      LAYER Metal3 ;
        RECT  0 788.98 0.4 789.38 ;
    END
  END push_block_i[149]
  PIN push_block_i[14]
    DIRECTION INPUT ;
    USE SIGNAL ;
    PORT
      LAYER Metal3 ;
        RECT  0 1015.78 0.4 1016.18 ;
    END
  END push_block_i[14]
  PIN push_block_i[150]
    DIRECTION INPUT ;
    USE SIGNAL ;
    PORT
      LAYER Metal3 ;
        RECT  0 787.3 0.4 787.7 ;
    END
  END push_block_i[150]
  PIN push_block_i[151]
    DIRECTION INPUT ;
    USE SIGNAL ;
    PORT
      LAYER Metal3 ;
        RECT  0 785.62 0.4 786.02 ;
    END
  END push_block_i[151]
  PIN push_block_i[152]
    DIRECTION INPUT ;
    USE SIGNAL ;
    PORT
      LAYER Metal3 ;
        RECT  0 783.94 0.4 784.34 ;
    END
  END push_block_i[152]
  PIN push_block_i[153]
    DIRECTION INPUT ;
    USE SIGNAL ;
    PORT
      LAYER Metal3 ;
        RECT  0 782.26 0.4 782.66 ;
    END
  END push_block_i[153]
  PIN push_block_i[154]
    DIRECTION INPUT ;
    USE SIGNAL ;
    PORT
      LAYER Metal3 ;
        RECT  0 780.58 0.4 780.98 ;
    END
  END push_block_i[154]
  PIN push_block_i[155]
    DIRECTION INPUT ;
    USE SIGNAL ;
    PORT
      LAYER Metal3 ;
        RECT  0 778.9 0.4 779.3 ;
    END
  END push_block_i[155]
  PIN push_block_i[156]
    DIRECTION INPUT ;
    USE SIGNAL ;
    PORT
      LAYER Metal3 ;
        RECT  0 777.22 0.4 777.62 ;
    END
  END push_block_i[156]
  PIN push_block_i[157]
    DIRECTION INPUT ;
    USE SIGNAL ;
    PORT
      LAYER Metal3 ;
        RECT  0 775.54 0.4 775.94 ;
    END
  END push_block_i[157]
  PIN push_block_i[158]
    DIRECTION INPUT ;
    USE SIGNAL ;
    PORT
      LAYER Metal3 ;
        RECT  0 773.86 0.4 774.26 ;
    END
  END push_block_i[158]
  PIN push_block_i[159]
    DIRECTION INPUT ;
    USE SIGNAL ;
    PORT
      LAYER Metal3 ;
        RECT  0 772.18 0.4 772.58 ;
    END
  END push_block_i[159]
  PIN push_block_i[15]
    DIRECTION INPUT ;
    USE SIGNAL ;
    PORT
      LAYER Metal3 ;
        RECT  0 1014.1 0.4 1014.5 ;
    END
  END push_block_i[15]
  PIN push_block_i[160]
    DIRECTION INPUT ;
    USE SIGNAL ;
    PORT
      LAYER Metal3 ;
        RECT  0 770.5 0.4 770.9 ;
    END
  END push_block_i[160]
  PIN push_block_i[161]
    DIRECTION INPUT ;
    USE SIGNAL ;
    PORT
      LAYER Metal3 ;
        RECT  0 768.82 0.4 769.22 ;
    END
  END push_block_i[161]
  PIN push_block_i[162]
    DIRECTION INPUT ;
    USE SIGNAL ;
    PORT
      LAYER Metal3 ;
        RECT  0 767.14 0.4 767.54 ;
    END
  END push_block_i[162]
  PIN push_block_i[163]
    DIRECTION INPUT ;
    USE SIGNAL ;
    PORT
      LAYER Metal3 ;
        RECT  0 765.46 0.4 765.86 ;
    END
  END push_block_i[163]
  PIN push_block_i[164]
    DIRECTION INPUT ;
    USE SIGNAL ;
    PORT
      LAYER Metal3 ;
        RECT  0 763.78 0.4 764.18 ;
    END
  END push_block_i[164]
  PIN push_block_i[165]
    DIRECTION INPUT ;
    USE SIGNAL ;
    PORT
      LAYER Metal3 ;
        RECT  0 762.1 0.4 762.5 ;
    END
  END push_block_i[165]
  PIN push_block_i[166]
    DIRECTION INPUT ;
    USE SIGNAL ;
    PORT
      LAYER Metal3 ;
        RECT  0 760.42 0.4 760.82 ;
    END
  END push_block_i[166]
  PIN push_block_i[167]
    DIRECTION INPUT ;
    USE SIGNAL ;
    PORT
      LAYER Metal3 ;
        RECT  0 758.74 0.4 759.14 ;
    END
  END push_block_i[167]
  PIN push_block_i[168]
    DIRECTION INPUT ;
    USE SIGNAL ;
    PORT
      LAYER Metal3 ;
        RECT  0 757.06 0.4 757.46 ;
    END
  END push_block_i[168]
  PIN push_block_i[169]
    DIRECTION INPUT ;
    USE SIGNAL ;
    PORT
      LAYER Metal3 ;
        RECT  0 755.38 0.4 755.78 ;
    END
  END push_block_i[169]
  PIN push_block_i[16]
    DIRECTION INPUT ;
    USE SIGNAL ;
    PORT
      LAYER Metal3 ;
        RECT  0 1012.42 0.4 1012.82 ;
    END
  END push_block_i[16]
  PIN push_block_i[170]
    DIRECTION INPUT ;
    USE SIGNAL ;
    PORT
      LAYER Metal3 ;
        RECT  0 753.7 0.4 754.1 ;
    END
  END push_block_i[170]
  PIN push_block_i[171]
    DIRECTION INPUT ;
    USE SIGNAL ;
    PORT
      LAYER Metal3 ;
        RECT  0 752.02 0.4 752.42 ;
    END
  END push_block_i[171]
  PIN push_block_i[172]
    DIRECTION INPUT ;
    USE SIGNAL ;
    PORT
      LAYER Metal3 ;
        RECT  0 750.34 0.4 750.74 ;
    END
  END push_block_i[172]
  PIN push_block_i[173]
    DIRECTION INPUT ;
    USE SIGNAL ;
    PORT
      LAYER Metal3 ;
        RECT  0 748.66 0.4 749.06 ;
    END
  END push_block_i[173]
  PIN push_block_i[174]
    DIRECTION INPUT ;
    USE SIGNAL ;
    PORT
      LAYER Metal3 ;
        RECT  0 746.98 0.4 747.38 ;
    END
  END push_block_i[174]
  PIN push_block_i[175]
    DIRECTION INPUT ;
    USE SIGNAL ;
    PORT
      LAYER Metal3 ;
        RECT  0 745.3 0.4 745.7 ;
    END
  END push_block_i[175]
  PIN push_block_i[176]
    DIRECTION INPUT ;
    USE SIGNAL ;
    PORT
      LAYER Metal3 ;
        RECT  0 743.62 0.4 744.02 ;
    END
  END push_block_i[176]
  PIN push_block_i[177]
    DIRECTION INPUT ;
    USE SIGNAL ;
    PORT
      LAYER Metal3 ;
        RECT  0 741.94 0.4 742.34 ;
    END
  END push_block_i[177]
  PIN push_block_i[178]
    DIRECTION INPUT ;
    USE SIGNAL ;
    PORT
      LAYER Metal3 ;
        RECT  0 740.26 0.4 740.66 ;
    END
  END push_block_i[178]
  PIN push_block_i[179]
    DIRECTION INPUT ;
    USE SIGNAL ;
    PORT
      LAYER Metal3 ;
        RECT  0 738.58 0.4 738.98 ;
    END
  END push_block_i[179]
  PIN push_block_i[17]
    DIRECTION INPUT ;
    USE SIGNAL ;
    PORT
      LAYER Metal3 ;
        RECT  0 1010.74 0.4 1011.14 ;
    END
  END push_block_i[17]
  PIN push_block_i[180]
    DIRECTION INPUT ;
    USE SIGNAL ;
    PORT
      LAYER Metal3 ;
        RECT  0 736.9 0.4 737.3 ;
    END
  END push_block_i[180]
  PIN push_block_i[181]
    DIRECTION INPUT ;
    USE SIGNAL ;
    PORT
      LAYER Metal3 ;
        RECT  0 735.22 0.4 735.62 ;
    END
  END push_block_i[181]
  PIN push_block_i[182]
    DIRECTION INPUT ;
    USE SIGNAL ;
    PORT
      LAYER Metal3 ;
        RECT  0 733.54 0.4 733.94 ;
    END
  END push_block_i[182]
  PIN push_block_i[183]
    DIRECTION INPUT ;
    USE SIGNAL ;
    PORT
      LAYER Metal3 ;
        RECT  0 731.86 0.4 732.26 ;
    END
  END push_block_i[183]
  PIN push_block_i[184]
    DIRECTION INPUT ;
    USE SIGNAL ;
    PORT
      LAYER Metal3 ;
        RECT  0 730.18 0.4 730.58 ;
    END
  END push_block_i[184]
  PIN push_block_i[185]
    DIRECTION INPUT ;
    USE SIGNAL ;
    PORT
      LAYER Metal3 ;
        RECT  0 728.5 0.4 728.9 ;
    END
  END push_block_i[185]
  PIN push_block_i[186]
    DIRECTION INPUT ;
    USE SIGNAL ;
    PORT
      LAYER Metal3 ;
        RECT  0 726.82 0.4 727.22 ;
    END
  END push_block_i[186]
  PIN push_block_i[187]
    DIRECTION INPUT ;
    USE SIGNAL ;
    PORT
      LAYER Metal3 ;
        RECT  0 725.14 0.4 725.54 ;
    END
  END push_block_i[187]
  PIN push_block_i[188]
    DIRECTION INPUT ;
    USE SIGNAL ;
    PORT
      LAYER Metal3 ;
        RECT  0 723.46 0.4 723.86 ;
    END
  END push_block_i[188]
  PIN push_block_i[189]
    DIRECTION INPUT ;
    USE SIGNAL ;
    PORT
      LAYER Metal3 ;
        RECT  0 721.78 0.4 722.18 ;
    END
  END push_block_i[189]
  PIN push_block_i[18]
    DIRECTION INPUT ;
    USE SIGNAL ;
    PORT
      LAYER Metal3 ;
        RECT  0 1009.06 0.4 1009.46 ;
    END
  END push_block_i[18]
  PIN push_block_i[190]
    DIRECTION INPUT ;
    USE SIGNAL ;
    PORT
      LAYER Metal3 ;
        RECT  0 720.1 0.4 720.5 ;
    END
  END push_block_i[190]
  PIN push_block_i[191]
    DIRECTION INPUT ;
    USE SIGNAL ;
    PORT
      LAYER Metal3 ;
        RECT  0 718.42 0.4 718.82 ;
    END
  END push_block_i[191]
  PIN push_block_i[192]
    DIRECTION INPUT ;
    USE SIGNAL ;
    PORT
      LAYER Metal3 ;
        RECT  0 716.74 0.4 717.14 ;
    END
  END push_block_i[192]
  PIN push_block_i[193]
    DIRECTION INPUT ;
    USE SIGNAL ;
    PORT
      LAYER Metal3 ;
        RECT  0 715.06 0.4 715.46 ;
    END
  END push_block_i[193]
  PIN push_block_i[194]
    DIRECTION INPUT ;
    USE SIGNAL ;
    PORT
      LAYER Metal3 ;
        RECT  0 713.38 0.4 713.78 ;
    END
  END push_block_i[194]
  PIN push_block_i[195]
    DIRECTION INPUT ;
    USE SIGNAL ;
    PORT
      LAYER Metal3 ;
        RECT  0 711.7 0.4 712.1 ;
    END
  END push_block_i[195]
  PIN push_block_i[196]
    DIRECTION INPUT ;
    USE SIGNAL ;
    PORT
      LAYER Metal3 ;
        RECT  0 710.02 0.4 710.42 ;
    END
  END push_block_i[196]
  PIN push_block_i[197]
    DIRECTION INPUT ;
    USE SIGNAL ;
    PORT
      LAYER Metal3 ;
        RECT  0 708.34 0.4 708.74 ;
    END
  END push_block_i[197]
  PIN push_block_i[198]
    DIRECTION INPUT ;
    USE SIGNAL ;
    PORT
      LAYER Metal3 ;
        RECT  0 706.66 0.4 707.06 ;
    END
  END push_block_i[198]
  PIN push_block_i[199]
    DIRECTION INPUT ;
    USE SIGNAL ;
    PORT
      LAYER Metal3 ;
        RECT  0 704.98 0.4 705.38 ;
    END
  END push_block_i[199]
  PIN push_block_i[19]
    DIRECTION INPUT ;
    USE SIGNAL ;
    PORT
      LAYER Metal3 ;
        RECT  0 1007.38 0.4 1007.78 ;
    END
  END push_block_i[19]
  PIN push_block_i[1]
    DIRECTION INPUT ;
    USE SIGNAL ;
    PORT
      LAYER Metal3 ;
        RECT  0 1037.62 0.4 1038.02 ;
    END
  END push_block_i[1]
  PIN push_block_i[200]
    DIRECTION INPUT ;
    USE SIGNAL ;
    PORT
      LAYER Metal3 ;
        RECT  0 703.3 0.4 703.7 ;
    END
  END push_block_i[200]
  PIN push_block_i[201]
    DIRECTION INPUT ;
    USE SIGNAL ;
    PORT
      LAYER Metal3 ;
        RECT  0 701.62 0.4 702.02 ;
    END
  END push_block_i[201]
  PIN push_block_i[202]
    DIRECTION INPUT ;
    USE SIGNAL ;
    PORT
      LAYER Metal3 ;
        RECT  0 699.94 0.4 700.34 ;
    END
  END push_block_i[202]
  PIN push_block_i[203]
    DIRECTION INPUT ;
    USE SIGNAL ;
    PORT
      LAYER Metal3 ;
        RECT  0 698.26 0.4 698.66 ;
    END
  END push_block_i[203]
  PIN push_block_i[204]
    DIRECTION INPUT ;
    USE SIGNAL ;
    PORT
      LAYER Metal3 ;
        RECT  0 696.58 0.4 696.98 ;
    END
  END push_block_i[204]
  PIN push_block_i[205]
    DIRECTION INPUT ;
    USE SIGNAL ;
    PORT
      LAYER Metal3 ;
        RECT  0 694.9 0.4 695.3 ;
    END
  END push_block_i[205]
  PIN push_block_i[206]
    DIRECTION INPUT ;
    USE SIGNAL ;
    PORT
      LAYER Metal3 ;
        RECT  0 693.22 0.4 693.62 ;
    END
  END push_block_i[206]
  PIN push_block_i[207]
    DIRECTION INPUT ;
    USE SIGNAL ;
    PORT
      LAYER Metal3 ;
        RECT  0 691.54 0.4 691.94 ;
    END
  END push_block_i[207]
  PIN push_block_i[208]
    DIRECTION INPUT ;
    USE SIGNAL ;
    PORT
      LAYER Metal3 ;
        RECT  0 689.86 0.4 690.26 ;
    END
  END push_block_i[208]
  PIN push_block_i[209]
    DIRECTION INPUT ;
    USE SIGNAL ;
    PORT
      LAYER Metal3 ;
        RECT  0 688.18 0.4 688.58 ;
    END
  END push_block_i[209]
  PIN push_block_i[20]
    DIRECTION INPUT ;
    USE SIGNAL ;
    PORT
      LAYER Metal3 ;
        RECT  0 1005.7 0.4 1006.1 ;
    END
  END push_block_i[20]
  PIN push_block_i[210]
    DIRECTION INPUT ;
    USE SIGNAL ;
    PORT
      LAYER Metal3 ;
        RECT  0 686.5 0.4 686.9 ;
    END
  END push_block_i[210]
  PIN push_block_i[211]
    DIRECTION INPUT ;
    USE SIGNAL ;
    PORT
      LAYER Metal3 ;
        RECT  0 684.82 0.4 685.22 ;
    END
  END push_block_i[211]
  PIN push_block_i[212]
    DIRECTION INPUT ;
    USE SIGNAL ;
    PORT
      LAYER Metal3 ;
        RECT  0 683.14 0.4 683.54 ;
    END
  END push_block_i[212]
  PIN push_block_i[213]
    DIRECTION INPUT ;
    USE SIGNAL ;
    PORT
      LAYER Metal3 ;
        RECT  0 681.46 0.4 681.86 ;
    END
  END push_block_i[213]
  PIN push_block_i[214]
    DIRECTION INPUT ;
    USE SIGNAL ;
    PORT
      LAYER Metal3 ;
        RECT  0 679.78 0.4 680.18 ;
    END
  END push_block_i[214]
  PIN push_block_i[215]
    DIRECTION INPUT ;
    USE SIGNAL ;
    PORT
      LAYER Metal3 ;
        RECT  0 678.1 0.4 678.5 ;
    END
  END push_block_i[215]
  PIN push_block_i[216]
    DIRECTION INPUT ;
    USE SIGNAL ;
    PORT
      LAYER Metal3 ;
        RECT  0 676.42 0.4 676.82 ;
    END
  END push_block_i[216]
  PIN push_block_i[217]
    DIRECTION INPUT ;
    USE SIGNAL ;
    PORT
      LAYER Metal3 ;
        RECT  0 674.74 0.4 675.14 ;
    END
  END push_block_i[217]
  PIN push_block_i[218]
    DIRECTION INPUT ;
    USE SIGNAL ;
    PORT
      LAYER Metal3 ;
        RECT  0 673.06 0.4 673.46 ;
    END
  END push_block_i[218]
  PIN push_block_i[219]
    DIRECTION INPUT ;
    USE SIGNAL ;
    PORT
      LAYER Metal3 ;
        RECT  0 671.38 0.4 671.78 ;
    END
  END push_block_i[219]
  PIN push_block_i[21]
    DIRECTION INPUT ;
    USE SIGNAL ;
    PORT
      LAYER Metal3 ;
        RECT  0 1004.02 0.4 1004.42 ;
    END
  END push_block_i[21]
  PIN push_block_i[220]
    DIRECTION INPUT ;
    USE SIGNAL ;
    PORT
      LAYER Metal3 ;
        RECT  0 669.7 0.4 670.1 ;
    END
  END push_block_i[220]
  PIN push_block_i[221]
    DIRECTION INPUT ;
    USE SIGNAL ;
    PORT
      LAYER Metal3 ;
        RECT  0 668.02 0.4 668.42 ;
    END
  END push_block_i[221]
  PIN push_block_i[222]
    DIRECTION INPUT ;
    USE SIGNAL ;
    PORT
      LAYER Metal3 ;
        RECT  0 666.34 0.4 666.74 ;
    END
  END push_block_i[222]
  PIN push_block_i[223]
    DIRECTION INPUT ;
    USE SIGNAL ;
    PORT
      LAYER Metal3 ;
        RECT  0 664.66 0.4 665.06 ;
    END
  END push_block_i[223]
  PIN push_block_i[224]
    DIRECTION INPUT ;
    USE SIGNAL ;
    PORT
      LAYER Metal3 ;
        RECT  0 662.98 0.4 663.38 ;
    END
  END push_block_i[224]
  PIN push_block_i[225]
    DIRECTION INPUT ;
    USE SIGNAL ;
    PORT
      LAYER Metal3 ;
        RECT  0 661.3 0.4 661.7 ;
    END
  END push_block_i[225]
  PIN push_block_i[226]
    DIRECTION INPUT ;
    USE SIGNAL ;
    PORT
      LAYER Metal3 ;
        RECT  0 659.62 0.4 660.02 ;
    END
  END push_block_i[226]
  PIN push_block_i[227]
    DIRECTION INPUT ;
    USE SIGNAL ;
    PORT
      LAYER Metal3 ;
        RECT  0 657.94 0.4 658.34 ;
    END
  END push_block_i[227]
  PIN push_block_i[228]
    DIRECTION INPUT ;
    USE SIGNAL ;
    PORT
      LAYER Metal3 ;
        RECT  0 656.26 0.4 656.66 ;
    END
  END push_block_i[228]
  PIN push_block_i[229]
    DIRECTION INPUT ;
    USE SIGNAL ;
    PORT
      LAYER Metal3 ;
        RECT  0 654.58 0.4 654.98 ;
    END
  END push_block_i[229]
  PIN push_block_i[22]
    DIRECTION INPUT ;
    USE SIGNAL ;
    PORT
      LAYER Metal3 ;
        RECT  0 1002.34 0.4 1002.74 ;
    END
  END push_block_i[22]
  PIN push_block_i[230]
    DIRECTION INPUT ;
    USE SIGNAL ;
    PORT
      LAYER Metal3 ;
        RECT  0 652.9 0.4 653.3 ;
    END
  END push_block_i[230]
  PIN push_block_i[231]
    DIRECTION INPUT ;
    USE SIGNAL ;
    PORT
      LAYER Metal3 ;
        RECT  0 651.22 0.4 651.62 ;
    END
  END push_block_i[231]
  PIN push_block_i[232]
    DIRECTION INPUT ;
    USE SIGNAL ;
    PORT
      LAYER Metal3 ;
        RECT  0 649.54 0.4 649.94 ;
    END
  END push_block_i[232]
  PIN push_block_i[233]
    DIRECTION INPUT ;
    USE SIGNAL ;
    PORT
      LAYER Metal3 ;
        RECT  0 647.86 0.4 648.26 ;
    END
  END push_block_i[233]
  PIN push_block_i[234]
    DIRECTION INPUT ;
    USE SIGNAL ;
    PORT
      LAYER Metal3 ;
        RECT  0 646.18 0.4 646.58 ;
    END
  END push_block_i[234]
  PIN push_block_i[235]
    DIRECTION INPUT ;
    USE SIGNAL ;
    PORT
      LAYER Metal3 ;
        RECT  0 644.5 0.4 644.9 ;
    END
  END push_block_i[235]
  PIN push_block_i[236]
    DIRECTION INPUT ;
    USE SIGNAL ;
    PORT
      LAYER Metal3 ;
        RECT  0 642.82 0.4 643.22 ;
    END
  END push_block_i[236]
  PIN push_block_i[237]
    DIRECTION INPUT ;
    USE SIGNAL ;
    PORT
      LAYER Metal3 ;
        RECT  0 641.14 0.4 641.54 ;
    END
  END push_block_i[237]
  PIN push_block_i[238]
    DIRECTION INPUT ;
    USE SIGNAL ;
    PORT
      LAYER Metal3 ;
        RECT  0 639.46 0.4 639.86 ;
    END
  END push_block_i[238]
  PIN push_block_i[239]
    DIRECTION INPUT ;
    USE SIGNAL ;
    PORT
      LAYER Metal3 ;
        RECT  0 637.78 0.4 638.18 ;
    END
  END push_block_i[239]
  PIN push_block_i[23]
    DIRECTION INPUT ;
    USE SIGNAL ;
    PORT
      LAYER Metal3 ;
        RECT  0 1000.66 0.4 1001.06 ;
    END
  END push_block_i[23]
  PIN push_block_i[240]
    DIRECTION INPUT ;
    USE SIGNAL ;
    PORT
      LAYER Metal3 ;
        RECT  0 636.1 0.4 636.5 ;
    END
  END push_block_i[240]
  PIN push_block_i[241]
    DIRECTION INPUT ;
    USE SIGNAL ;
    PORT
      LAYER Metal3 ;
        RECT  0 634.42 0.4 634.82 ;
    END
  END push_block_i[241]
  PIN push_block_i[242]
    DIRECTION INPUT ;
    USE SIGNAL ;
    PORT
      LAYER Metal3 ;
        RECT  0 632.74 0.4 633.14 ;
    END
  END push_block_i[242]
  PIN push_block_i[243]
    DIRECTION INPUT ;
    USE SIGNAL ;
    PORT
      LAYER Metal3 ;
        RECT  0 631.06 0.4 631.46 ;
    END
  END push_block_i[243]
  PIN push_block_i[244]
    DIRECTION INPUT ;
    USE SIGNAL ;
    PORT
      LAYER Metal3 ;
        RECT  0 629.38 0.4 629.78 ;
    END
  END push_block_i[244]
  PIN push_block_i[245]
    DIRECTION INPUT ;
    USE SIGNAL ;
    PORT
      LAYER Metal3 ;
        RECT  0 627.7 0.4 628.1 ;
    END
  END push_block_i[245]
  PIN push_block_i[246]
    DIRECTION INPUT ;
    USE SIGNAL ;
    PORT
      LAYER Metal3 ;
        RECT  0 626.02 0.4 626.42 ;
    END
  END push_block_i[246]
  PIN push_block_i[247]
    DIRECTION INPUT ;
    USE SIGNAL ;
    PORT
      LAYER Metal3 ;
        RECT  0 624.34 0.4 624.74 ;
    END
  END push_block_i[247]
  PIN push_block_i[248]
    DIRECTION INPUT ;
    USE SIGNAL ;
    PORT
      LAYER Metal3 ;
        RECT  0 622.66 0.4 623.06 ;
    END
  END push_block_i[248]
  PIN push_block_i[249]
    DIRECTION INPUT ;
    USE SIGNAL ;
    PORT
      LAYER Metal3 ;
        RECT  0 620.98 0.4 621.38 ;
    END
  END push_block_i[249]
  PIN push_block_i[24]
    DIRECTION INPUT ;
    USE SIGNAL ;
    PORT
      LAYER Metal3 ;
        RECT  0 998.98 0.4 999.38 ;
    END
  END push_block_i[24]
  PIN push_block_i[250]
    DIRECTION INPUT ;
    USE SIGNAL ;
    PORT
      LAYER Metal3 ;
        RECT  0 619.3 0.4 619.7 ;
    END
  END push_block_i[250]
  PIN push_block_i[251]
    DIRECTION INPUT ;
    USE SIGNAL ;
    PORT
      LAYER Metal3 ;
        RECT  0 617.62 0.4 618.02 ;
    END
  END push_block_i[251]
  PIN push_block_i[252]
    DIRECTION INPUT ;
    USE SIGNAL ;
    PORT
      LAYER Metal3 ;
        RECT  0 615.94 0.4 616.34 ;
    END
  END push_block_i[252]
  PIN push_block_i[253]
    DIRECTION INPUT ;
    USE SIGNAL ;
    PORT
      LAYER Metal3 ;
        RECT  0 614.26 0.4 614.66 ;
    END
  END push_block_i[253]
  PIN push_block_i[254]
    DIRECTION INPUT ;
    USE SIGNAL ;
    PORT
      LAYER Metal3 ;
        RECT  0 612.58 0.4 612.98 ;
    END
  END push_block_i[254]
  PIN push_block_i[255]
    DIRECTION INPUT ;
    USE SIGNAL ;
    PORT
      LAYER Metal3 ;
        RECT  0 610.9 0.4 611.3 ;
    END
  END push_block_i[255]
  PIN push_block_i[256]
    DIRECTION INPUT ;
    USE SIGNAL ;
    PORT
      LAYER Metal3 ;
        RECT  0 609.22 0.4 609.62 ;
    END
  END push_block_i[256]
  PIN push_block_i[257]
    DIRECTION INPUT ;
    USE SIGNAL ;
    PORT
      LAYER Metal3 ;
        RECT  0 607.54 0.4 607.94 ;
    END
  END push_block_i[257]
  PIN push_block_i[258]
    DIRECTION INPUT ;
    USE SIGNAL ;
    PORT
      LAYER Metal3 ;
        RECT  0 605.86 0.4 606.26 ;
    END
  END push_block_i[258]
  PIN push_block_i[259]
    DIRECTION INPUT ;
    USE SIGNAL ;
    PORT
      LAYER Metal3 ;
        RECT  0 604.18 0.4 604.58 ;
    END
  END push_block_i[259]
  PIN push_block_i[25]
    DIRECTION INPUT ;
    USE SIGNAL ;
    PORT
      LAYER Metal3 ;
        RECT  0 997.3 0.4 997.7 ;
    END
  END push_block_i[25]
  PIN push_block_i[260]
    DIRECTION INPUT ;
    USE SIGNAL ;
    PORT
      LAYER Metal3 ;
        RECT  0 602.5 0.4 602.9 ;
    END
  END push_block_i[260]
  PIN push_block_i[261]
    DIRECTION INPUT ;
    USE SIGNAL ;
    PORT
      LAYER Metal3 ;
        RECT  0 600.82 0.4 601.22 ;
    END
  END push_block_i[261]
  PIN push_block_i[262]
    DIRECTION INPUT ;
    USE SIGNAL ;
    PORT
      LAYER Metal3 ;
        RECT  0 599.14 0.4 599.54 ;
    END
  END push_block_i[262]
  PIN push_block_i[263]
    DIRECTION INPUT ;
    USE SIGNAL ;
    PORT
      LAYER Metal3 ;
        RECT  0 597.46 0.4 597.86 ;
    END
  END push_block_i[263]
  PIN push_block_i[264]
    DIRECTION INPUT ;
    USE SIGNAL ;
    PORT
      LAYER Metal3 ;
        RECT  0 595.78 0.4 596.18 ;
    END
  END push_block_i[264]
  PIN push_block_i[265]
    DIRECTION INPUT ;
    USE SIGNAL ;
    PORT
      LAYER Metal3 ;
        RECT  0 594.1 0.4 594.5 ;
    END
  END push_block_i[265]
  PIN push_block_i[266]
    DIRECTION INPUT ;
    USE SIGNAL ;
    PORT
      LAYER Metal3 ;
        RECT  0 592.42 0.4 592.82 ;
    END
  END push_block_i[266]
  PIN push_block_i[267]
    DIRECTION INPUT ;
    USE SIGNAL ;
    PORT
      LAYER Metal3 ;
        RECT  0 590.74 0.4 591.14 ;
    END
  END push_block_i[267]
  PIN push_block_i[268]
    DIRECTION INPUT ;
    USE SIGNAL ;
    PORT
      LAYER Metal3 ;
        RECT  0 589.06 0.4 589.46 ;
    END
  END push_block_i[268]
  PIN push_block_i[269]
    DIRECTION INPUT ;
    USE SIGNAL ;
    PORT
      LAYER Metal3 ;
        RECT  0 587.38 0.4 587.78 ;
    END
  END push_block_i[269]
  PIN push_block_i[26]
    DIRECTION INPUT ;
    USE SIGNAL ;
    PORT
      LAYER Metal3 ;
        RECT  0 995.62 0.4 996.02 ;
    END
  END push_block_i[26]
  PIN push_block_i[270]
    DIRECTION INPUT ;
    USE SIGNAL ;
    PORT
      LAYER Metal3 ;
        RECT  0 585.7 0.4 586.1 ;
    END
  END push_block_i[270]
  PIN push_block_i[271]
    DIRECTION INPUT ;
    USE SIGNAL ;
    PORT
      LAYER Metal3 ;
        RECT  0 584.02 0.4 584.42 ;
    END
  END push_block_i[271]
  PIN push_block_i[272]
    DIRECTION INPUT ;
    USE SIGNAL ;
    PORT
      LAYER Metal3 ;
        RECT  0 582.34 0.4 582.74 ;
    END
  END push_block_i[272]
  PIN push_block_i[273]
    DIRECTION INPUT ;
    USE SIGNAL ;
    PORT
      LAYER Metal3 ;
        RECT  0 580.66 0.4 581.06 ;
    END
  END push_block_i[273]
  PIN push_block_i[274]
    DIRECTION INPUT ;
    USE SIGNAL ;
    PORT
      LAYER Metal3 ;
        RECT  0 578.98 0.4 579.38 ;
    END
  END push_block_i[274]
  PIN push_block_i[275]
    DIRECTION INPUT ;
    USE SIGNAL ;
    PORT
      LAYER Metal3 ;
        RECT  0 577.3 0.4 577.7 ;
    END
  END push_block_i[275]
  PIN push_block_i[276]
    DIRECTION INPUT ;
    USE SIGNAL ;
    PORT
      LAYER Metal3 ;
        RECT  0 575.62 0.4 576.02 ;
    END
  END push_block_i[276]
  PIN push_block_i[277]
    DIRECTION INPUT ;
    USE SIGNAL ;
    PORT
      LAYER Metal3 ;
        RECT  0 573.94 0.4 574.34 ;
    END
  END push_block_i[277]
  PIN push_block_i[278]
    DIRECTION INPUT ;
    USE SIGNAL ;
    PORT
      LAYER Metal3 ;
        RECT  0 572.26 0.4 572.66 ;
    END
  END push_block_i[278]
  PIN push_block_i[279]
    DIRECTION INPUT ;
    USE SIGNAL ;
    PORT
      LAYER Metal3 ;
        RECT  0 570.58 0.4 570.98 ;
    END
  END push_block_i[279]
  PIN push_block_i[27]
    DIRECTION INPUT ;
    USE SIGNAL ;
    PORT
      LAYER Metal3 ;
        RECT  0 993.94 0.4 994.34 ;
    END
  END push_block_i[27]
  PIN push_block_i[280]
    DIRECTION INPUT ;
    USE SIGNAL ;
    PORT
      LAYER Metal3 ;
        RECT  0 568.9 0.4 569.3 ;
    END
  END push_block_i[280]
  PIN push_block_i[281]
    DIRECTION INPUT ;
    USE SIGNAL ;
    PORT
      LAYER Metal3 ;
        RECT  0 567.22 0.4 567.62 ;
    END
  END push_block_i[281]
  PIN push_block_i[282]
    DIRECTION INPUT ;
    USE SIGNAL ;
    PORT
      LAYER Metal3 ;
        RECT  0 565.54 0.4 565.94 ;
    END
  END push_block_i[282]
  PIN push_block_i[283]
    DIRECTION INPUT ;
    USE SIGNAL ;
    PORT
      LAYER Metal3 ;
        RECT  0 563.86 0.4 564.26 ;
    END
  END push_block_i[283]
  PIN push_block_i[284]
    DIRECTION INPUT ;
    USE SIGNAL ;
    PORT
      LAYER Metal3 ;
        RECT  0 562.18 0.4 562.58 ;
    END
  END push_block_i[284]
  PIN push_block_i[285]
    DIRECTION INPUT ;
    USE SIGNAL ;
    PORT
      LAYER Metal3 ;
        RECT  0 560.5 0.4 560.9 ;
    END
  END push_block_i[285]
  PIN push_block_i[286]
    DIRECTION INPUT ;
    USE SIGNAL ;
    PORT
      LAYER Metal3 ;
        RECT  0 558.82 0.4 559.22 ;
    END
  END push_block_i[286]
  PIN push_block_i[287]
    DIRECTION INPUT ;
    USE SIGNAL ;
    PORT
      LAYER Metal3 ;
        RECT  0 557.14 0.4 557.54 ;
    END
  END push_block_i[287]
  PIN push_block_i[288]
    DIRECTION INPUT ;
    USE SIGNAL ;
    PORT
      LAYER Metal3 ;
        RECT  0 555.46 0.4 555.86 ;
    END
  END push_block_i[288]
  PIN push_block_i[289]
    DIRECTION INPUT ;
    USE SIGNAL ;
    PORT
      LAYER Metal3 ;
        RECT  0 553.78 0.4 554.18 ;
    END
  END push_block_i[289]
  PIN push_block_i[28]
    DIRECTION INPUT ;
    USE SIGNAL ;
    PORT
      LAYER Metal3 ;
        RECT  0 992.26 0.4 992.66 ;
    END
  END push_block_i[28]
  PIN push_block_i[290]
    DIRECTION INPUT ;
    USE SIGNAL ;
    PORT
      LAYER Metal3 ;
        RECT  0 552.1 0.4 552.5 ;
    END
  END push_block_i[290]
  PIN push_block_i[291]
    DIRECTION INPUT ;
    USE SIGNAL ;
    PORT
      LAYER Metal3 ;
        RECT  0 550.42 0.4 550.82 ;
    END
  END push_block_i[291]
  PIN push_block_i[292]
    DIRECTION INPUT ;
    USE SIGNAL ;
    PORT
      LAYER Metal3 ;
        RECT  0 548.74 0.4 549.14 ;
    END
  END push_block_i[292]
  PIN push_block_i[293]
    DIRECTION INPUT ;
    USE SIGNAL ;
    PORT
      LAYER Metal3 ;
        RECT  0 547.06 0.4 547.46 ;
    END
  END push_block_i[293]
  PIN push_block_i[294]
    DIRECTION INPUT ;
    USE SIGNAL ;
    PORT
      LAYER Metal3 ;
        RECT  0 545.38 0.4 545.78 ;
    END
  END push_block_i[294]
  PIN push_block_i[295]
    DIRECTION INPUT ;
    USE SIGNAL ;
    PORT
      LAYER Metal3 ;
        RECT  0 543.7 0.4 544.1 ;
    END
  END push_block_i[295]
  PIN push_block_i[296]
    DIRECTION INPUT ;
    USE SIGNAL ;
    PORT
      LAYER Metal3 ;
        RECT  0 542.02 0.4 542.42 ;
    END
  END push_block_i[296]
  PIN push_block_i[297]
    DIRECTION INPUT ;
    USE SIGNAL ;
    PORT
      LAYER Metal3 ;
        RECT  0 540.34 0.4 540.74 ;
    END
  END push_block_i[297]
  PIN push_block_i[298]
    DIRECTION INPUT ;
    USE SIGNAL ;
    PORT
      LAYER Metal3 ;
        RECT  0 538.66 0.4 539.06 ;
    END
  END push_block_i[298]
  PIN push_block_i[299]
    DIRECTION INPUT ;
    USE SIGNAL ;
    PORT
      LAYER Metal3 ;
        RECT  0 536.98 0.4 537.38 ;
    END
  END push_block_i[299]
  PIN push_block_i[29]
    DIRECTION INPUT ;
    USE SIGNAL ;
    PORT
      LAYER Metal3 ;
        RECT  0 990.58 0.4 990.98 ;
    END
  END push_block_i[29]
  PIN push_block_i[2]
    DIRECTION INPUT ;
    USE SIGNAL ;
    PORT
      LAYER Metal3 ;
        RECT  0 1035.94 0.4 1036.34 ;
    END
  END push_block_i[2]
  PIN push_block_i[300]
    DIRECTION INPUT ;
    USE SIGNAL ;
    PORT
      LAYER Metal3 ;
        RECT  0 535.3 0.4 535.7 ;
    END
  END push_block_i[300]
  PIN push_block_i[301]
    DIRECTION INPUT ;
    USE SIGNAL ;
    PORT
      LAYER Metal3 ;
        RECT  0 533.62 0.4 534.02 ;
    END
  END push_block_i[301]
  PIN push_block_i[302]
    DIRECTION INPUT ;
    USE SIGNAL ;
    PORT
      LAYER Metal3 ;
        RECT  0 531.94 0.4 532.34 ;
    END
  END push_block_i[302]
  PIN push_block_i[303]
    DIRECTION INPUT ;
    USE SIGNAL ;
    PORT
      LAYER Metal3 ;
        RECT  0 530.26 0.4 530.66 ;
    END
  END push_block_i[303]
  PIN push_block_i[304]
    DIRECTION INPUT ;
    USE SIGNAL ;
    PORT
      LAYER Metal3 ;
        RECT  0 528.58 0.4 528.98 ;
    END
  END push_block_i[304]
  PIN push_block_i[305]
    DIRECTION INPUT ;
    USE SIGNAL ;
    PORT
      LAYER Metal3 ;
        RECT  0 526.9 0.4 527.3 ;
    END
  END push_block_i[305]
  PIN push_block_i[306]
    DIRECTION INPUT ;
    USE SIGNAL ;
    PORT
      LAYER Metal3 ;
        RECT  0 525.22 0.4 525.62 ;
    END
  END push_block_i[306]
  PIN push_block_i[307]
    DIRECTION INPUT ;
    USE SIGNAL ;
    PORT
      LAYER Metal3 ;
        RECT  0 523.54 0.4 523.94 ;
    END
  END push_block_i[307]
  PIN push_block_i[308]
    DIRECTION INPUT ;
    USE SIGNAL ;
    PORT
      LAYER Metal3 ;
        RECT  0 521.86 0.4 522.26 ;
    END
  END push_block_i[308]
  PIN push_block_i[309]
    DIRECTION INPUT ;
    USE SIGNAL ;
    PORT
      LAYER Metal3 ;
        RECT  0 520.18 0.4 520.58 ;
    END
  END push_block_i[309]
  PIN push_block_i[30]
    DIRECTION INPUT ;
    USE SIGNAL ;
    PORT
      LAYER Metal3 ;
        RECT  0 988.9 0.4 989.3 ;
    END
  END push_block_i[30]
  PIN push_block_i[310]
    DIRECTION INPUT ;
    USE SIGNAL ;
    PORT
      LAYER Metal3 ;
        RECT  0 518.5 0.4 518.9 ;
    END
  END push_block_i[310]
  PIN push_block_i[311]
    DIRECTION INPUT ;
    USE SIGNAL ;
    PORT
      LAYER Metal3 ;
        RECT  0 516.82 0.4 517.22 ;
    END
  END push_block_i[311]
  PIN push_block_i[312]
    DIRECTION INPUT ;
    USE SIGNAL ;
    PORT
      LAYER Metal3 ;
        RECT  0 515.14 0.4 515.54 ;
    END
  END push_block_i[312]
  PIN push_block_i[313]
    DIRECTION INPUT ;
    USE SIGNAL ;
    PORT
      LAYER Metal3 ;
        RECT  0 513.46 0.4 513.86 ;
    END
  END push_block_i[313]
  PIN push_block_i[314]
    DIRECTION INPUT ;
    USE SIGNAL ;
    PORT
      LAYER Metal3 ;
        RECT  0 511.78 0.4 512.18 ;
    END
  END push_block_i[314]
  PIN push_block_i[315]
    DIRECTION INPUT ;
    USE SIGNAL ;
    PORT
      LAYER Metal3 ;
        RECT  0 510.1 0.4 510.5 ;
    END
  END push_block_i[315]
  PIN push_block_i[316]
    DIRECTION INPUT ;
    USE SIGNAL ;
    PORT
      LAYER Metal3 ;
        RECT  0 508.42 0.4 508.82 ;
    END
  END push_block_i[316]
  PIN push_block_i[317]
    DIRECTION INPUT ;
    USE SIGNAL ;
    PORT
      LAYER Metal3 ;
        RECT  0 506.74 0.4 507.14 ;
    END
  END push_block_i[317]
  PIN push_block_i[318]
    DIRECTION INPUT ;
    USE SIGNAL ;
    PORT
      LAYER Metal3 ;
        RECT  0 505.06 0.4 505.46 ;
    END
  END push_block_i[318]
  PIN push_block_i[319]
    DIRECTION INPUT ;
    USE SIGNAL ;
    PORT
      LAYER Metal3 ;
        RECT  0 503.38 0.4 503.78 ;
    END
  END push_block_i[319]
  PIN push_block_i[31]
    DIRECTION INPUT ;
    USE SIGNAL ;
    PORT
      LAYER Metal3 ;
        RECT  0 987.22 0.4 987.62 ;
    END
  END push_block_i[31]
  PIN push_block_i[320]
    DIRECTION INPUT ;
    USE SIGNAL ;
    PORT
      LAYER Metal3 ;
        RECT  0 501.7 0.4 502.1 ;
    END
  END push_block_i[320]
  PIN push_block_i[321]
    DIRECTION INPUT ;
    USE SIGNAL ;
    PORT
      LAYER Metal3 ;
        RECT  0 500.02 0.4 500.42 ;
    END
  END push_block_i[321]
  PIN push_block_i[322]
    DIRECTION INPUT ;
    USE SIGNAL ;
    PORT
      LAYER Metal3 ;
        RECT  0 498.34 0.4 498.74 ;
    END
  END push_block_i[322]
  PIN push_block_i[323]
    DIRECTION INPUT ;
    USE SIGNAL ;
    PORT
      LAYER Metal3 ;
        RECT  0 496.66 0.4 497.06 ;
    END
  END push_block_i[323]
  PIN push_block_i[324]
    DIRECTION INPUT ;
    USE SIGNAL ;
    PORT
      LAYER Metal3 ;
        RECT  0 494.98 0.4 495.38 ;
    END
  END push_block_i[324]
  PIN push_block_i[325]
    DIRECTION INPUT ;
    USE SIGNAL ;
    PORT
      LAYER Metal3 ;
        RECT  0 493.3 0.4 493.7 ;
    END
  END push_block_i[325]
  PIN push_block_i[326]
    DIRECTION INPUT ;
    USE SIGNAL ;
    PORT
      LAYER Metal3 ;
        RECT  0 491.62 0.4 492.02 ;
    END
  END push_block_i[326]
  PIN push_block_i[327]
    DIRECTION INPUT ;
    USE SIGNAL ;
    PORT
      LAYER Metal3 ;
        RECT  0 489.94 0.4 490.34 ;
    END
  END push_block_i[327]
  PIN push_block_i[328]
    DIRECTION INPUT ;
    USE SIGNAL ;
    PORT
      LAYER Metal3 ;
        RECT  0 488.26 0.4 488.66 ;
    END
  END push_block_i[328]
  PIN push_block_i[329]
    DIRECTION INPUT ;
    USE SIGNAL ;
    PORT
      LAYER Metal3 ;
        RECT  0 486.58 0.4 486.98 ;
    END
  END push_block_i[329]
  PIN push_block_i[32]
    DIRECTION INPUT ;
    USE SIGNAL ;
    PORT
      LAYER Metal3 ;
        RECT  0 985.54 0.4 985.94 ;
    END
  END push_block_i[32]
  PIN push_block_i[330]
    DIRECTION INPUT ;
    USE SIGNAL ;
    PORT
      LAYER Metal3 ;
        RECT  0 484.9 0.4 485.3 ;
    END
  END push_block_i[330]
  PIN push_block_i[331]
    DIRECTION INPUT ;
    USE SIGNAL ;
    PORT
      LAYER Metal3 ;
        RECT  0 483.22 0.4 483.62 ;
    END
  END push_block_i[331]
  PIN push_block_i[332]
    DIRECTION INPUT ;
    USE SIGNAL ;
    PORT
      LAYER Metal3 ;
        RECT  0 481.54 0.4 481.94 ;
    END
  END push_block_i[332]
  PIN push_block_i[333]
    DIRECTION INPUT ;
    USE SIGNAL ;
    PORT
      LAYER Metal3 ;
        RECT  0 479.86 0.4 480.26 ;
    END
  END push_block_i[333]
  PIN push_block_i[334]
    DIRECTION INPUT ;
    USE SIGNAL ;
    PORT
      LAYER Metal3 ;
        RECT  0 478.18 0.4 478.58 ;
    END
  END push_block_i[334]
  PIN push_block_i[335]
    DIRECTION INPUT ;
    USE SIGNAL ;
    PORT
      LAYER Metal3 ;
        RECT  0 476.5 0.4 476.9 ;
    END
  END push_block_i[335]
  PIN push_block_i[336]
    DIRECTION INPUT ;
    USE SIGNAL ;
    PORT
      LAYER Metal3 ;
        RECT  0 474.82 0.4 475.22 ;
    END
  END push_block_i[336]
  PIN push_block_i[337]
    DIRECTION INPUT ;
    USE SIGNAL ;
    PORT
      LAYER Metal3 ;
        RECT  0 473.14 0.4 473.54 ;
    END
  END push_block_i[337]
  PIN push_block_i[338]
    DIRECTION INPUT ;
    USE SIGNAL ;
    PORT
      LAYER Metal3 ;
        RECT  0 471.46 0.4 471.86 ;
    END
  END push_block_i[338]
  PIN push_block_i[339]
    DIRECTION INPUT ;
    USE SIGNAL ;
    PORT
      LAYER Metal3 ;
        RECT  0 469.78 0.4 470.18 ;
    END
  END push_block_i[339]
  PIN push_block_i[33]
    DIRECTION INPUT ;
    USE SIGNAL ;
    PORT
      LAYER Metal3 ;
        RECT  0 983.86 0.4 984.26 ;
    END
  END push_block_i[33]
  PIN push_block_i[340]
    DIRECTION INPUT ;
    USE SIGNAL ;
    PORT
      LAYER Metal3 ;
        RECT  0 468.1 0.4 468.5 ;
    END
  END push_block_i[340]
  PIN push_block_i[341]
    DIRECTION INPUT ;
    USE SIGNAL ;
    PORT
      LAYER Metal3 ;
        RECT  0 466.42 0.4 466.82 ;
    END
  END push_block_i[341]
  PIN push_block_i[342]
    DIRECTION INPUT ;
    USE SIGNAL ;
    PORT
      LAYER Metal3 ;
        RECT  0 464.74 0.4 465.14 ;
    END
  END push_block_i[342]
  PIN push_block_i[343]
    DIRECTION INPUT ;
    USE SIGNAL ;
    PORT
      LAYER Metal3 ;
        RECT  0 463.06 0.4 463.46 ;
    END
  END push_block_i[343]
  PIN push_block_i[344]
    DIRECTION INPUT ;
    USE SIGNAL ;
    PORT
      LAYER Metal3 ;
        RECT  0 461.38 0.4 461.78 ;
    END
  END push_block_i[344]
  PIN push_block_i[345]
    DIRECTION INPUT ;
    USE SIGNAL ;
    PORT
      LAYER Metal3 ;
        RECT  0 459.7 0.4 460.1 ;
    END
  END push_block_i[345]
  PIN push_block_i[346]
    DIRECTION INPUT ;
    USE SIGNAL ;
    PORT
      LAYER Metal3 ;
        RECT  0 458.02 0.4 458.42 ;
    END
  END push_block_i[346]
  PIN push_block_i[347]
    DIRECTION INPUT ;
    USE SIGNAL ;
    PORT
      LAYER Metal3 ;
        RECT  0 456.34 0.4 456.74 ;
    END
  END push_block_i[347]
  PIN push_block_i[348]
    DIRECTION INPUT ;
    USE SIGNAL ;
    PORT
      LAYER Metal3 ;
        RECT  0 454.66 0.4 455.06 ;
    END
  END push_block_i[348]
  PIN push_block_i[349]
    DIRECTION INPUT ;
    USE SIGNAL ;
    PORT
      LAYER Metal3 ;
        RECT  0 452.98 0.4 453.38 ;
    END
  END push_block_i[349]
  PIN push_block_i[34]
    DIRECTION INPUT ;
    USE SIGNAL ;
    PORT
      LAYER Metal3 ;
        RECT  0 982.18 0.4 982.58 ;
    END
  END push_block_i[34]
  PIN push_block_i[350]
    DIRECTION INPUT ;
    USE SIGNAL ;
    PORT
      LAYER Metal3 ;
        RECT  0 451.3 0.4 451.7 ;
    END
  END push_block_i[350]
  PIN push_block_i[351]
    DIRECTION INPUT ;
    USE SIGNAL ;
    PORT
      LAYER Metal3 ;
        RECT  0 449.62 0.4 450.02 ;
    END
  END push_block_i[351]
  PIN push_block_i[352]
    DIRECTION INPUT ;
    USE SIGNAL ;
    PORT
      LAYER Metal3 ;
        RECT  0 447.94 0.4 448.34 ;
    END
  END push_block_i[352]
  PIN push_block_i[353]
    DIRECTION INPUT ;
    USE SIGNAL ;
    PORT
      LAYER Metal3 ;
        RECT  0 446.26 0.4 446.66 ;
    END
  END push_block_i[353]
  PIN push_block_i[354]
    DIRECTION INPUT ;
    USE SIGNAL ;
    PORT
      LAYER Metal3 ;
        RECT  0 444.58 0.4 444.98 ;
    END
  END push_block_i[354]
  PIN push_block_i[355]
    DIRECTION INPUT ;
    USE SIGNAL ;
    PORT
      LAYER Metal3 ;
        RECT  0 442.9 0.4 443.3 ;
    END
  END push_block_i[355]
  PIN push_block_i[356]
    DIRECTION INPUT ;
    USE SIGNAL ;
    PORT
      LAYER Metal3 ;
        RECT  0 441.22 0.4 441.62 ;
    END
  END push_block_i[356]
  PIN push_block_i[357]
    DIRECTION INPUT ;
    USE SIGNAL ;
    PORT
      LAYER Metal3 ;
        RECT  0 439.54 0.4 439.94 ;
    END
  END push_block_i[357]
  PIN push_block_i[358]
    DIRECTION INPUT ;
    USE SIGNAL ;
    PORT
      LAYER Metal3 ;
        RECT  0 437.86 0.4 438.26 ;
    END
  END push_block_i[358]
  PIN push_block_i[359]
    DIRECTION INPUT ;
    USE SIGNAL ;
    PORT
      LAYER Metal3 ;
        RECT  0 436.18 0.4 436.58 ;
    END
  END push_block_i[359]
  PIN push_block_i[35]
    DIRECTION INPUT ;
    USE SIGNAL ;
    PORT
      LAYER Metal3 ;
        RECT  0 980.5 0.4 980.9 ;
    END
  END push_block_i[35]
  PIN push_block_i[360]
    DIRECTION INPUT ;
    USE SIGNAL ;
    PORT
      LAYER Metal3 ;
        RECT  0 434.5 0.4 434.9 ;
    END
  END push_block_i[360]
  PIN push_block_i[361]
    DIRECTION INPUT ;
    USE SIGNAL ;
    PORT
      LAYER Metal3 ;
        RECT  0 432.82 0.4 433.22 ;
    END
  END push_block_i[361]
  PIN push_block_i[362]
    DIRECTION INPUT ;
    USE SIGNAL ;
    PORT
      LAYER Metal3 ;
        RECT  0 431.14 0.4 431.54 ;
    END
  END push_block_i[362]
  PIN push_block_i[363]
    DIRECTION INPUT ;
    USE SIGNAL ;
    PORT
      LAYER Metal3 ;
        RECT  0 429.46 0.4 429.86 ;
    END
  END push_block_i[363]
  PIN push_block_i[364]
    DIRECTION INPUT ;
    USE SIGNAL ;
    PORT
      LAYER Metal3 ;
        RECT  0 427.78 0.4 428.18 ;
    END
  END push_block_i[364]
  PIN push_block_i[365]
    DIRECTION INPUT ;
    USE SIGNAL ;
    PORT
      LAYER Metal3 ;
        RECT  0 426.1 0.4 426.5 ;
    END
  END push_block_i[365]
  PIN push_block_i[366]
    DIRECTION INPUT ;
    USE SIGNAL ;
    PORT
      LAYER Metal3 ;
        RECT  0 424.42 0.4 424.82 ;
    END
  END push_block_i[366]
  PIN push_block_i[367]
    DIRECTION INPUT ;
    USE SIGNAL ;
    PORT
      LAYER Metal3 ;
        RECT  0 422.74 0.4 423.14 ;
    END
  END push_block_i[367]
  PIN push_block_i[368]
    DIRECTION INPUT ;
    USE SIGNAL ;
    PORT
      LAYER Metal3 ;
        RECT  0 421.06 0.4 421.46 ;
    END
  END push_block_i[368]
  PIN push_block_i[369]
    DIRECTION INPUT ;
    USE SIGNAL ;
    PORT
      LAYER Metal3 ;
        RECT  0 419.38 0.4 419.78 ;
    END
  END push_block_i[369]
  PIN push_block_i[36]
    DIRECTION INPUT ;
    USE SIGNAL ;
    PORT
      LAYER Metal3 ;
        RECT  0 978.82 0.4 979.22 ;
    END
  END push_block_i[36]
  PIN push_block_i[370]
    DIRECTION INPUT ;
    USE SIGNAL ;
    PORT
      LAYER Metal3 ;
        RECT  0 417.7 0.4 418.1 ;
    END
  END push_block_i[370]
  PIN push_block_i[371]
    DIRECTION INPUT ;
    USE SIGNAL ;
    PORT
      LAYER Metal3 ;
        RECT  0 416.02 0.4 416.42 ;
    END
  END push_block_i[371]
  PIN push_block_i[372]
    DIRECTION INPUT ;
    USE SIGNAL ;
    PORT
      LAYER Metal3 ;
        RECT  0 414.34 0.4 414.74 ;
    END
  END push_block_i[372]
  PIN push_block_i[373]
    DIRECTION INPUT ;
    USE SIGNAL ;
    PORT
      LAYER Metal3 ;
        RECT  0 412.66 0.4 413.06 ;
    END
  END push_block_i[373]
  PIN push_block_i[374]
    DIRECTION INPUT ;
    USE SIGNAL ;
    PORT
      LAYER Metal3 ;
        RECT  0 410.98 0.4 411.38 ;
    END
  END push_block_i[374]
  PIN push_block_i[375]
    DIRECTION INPUT ;
    USE SIGNAL ;
    PORT
      LAYER Metal3 ;
        RECT  0 409.3 0.4 409.7 ;
    END
  END push_block_i[375]
  PIN push_block_i[376]
    DIRECTION INPUT ;
    USE SIGNAL ;
    PORT
      LAYER Metal3 ;
        RECT  0 407.62 0.4 408.02 ;
    END
  END push_block_i[376]
  PIN push_block_i[377]
    DIRECTION INPUT ;
    USE SIGNAL ;
    PORT
      LAYER Metal3 ;
        RECT  0 405.94 0.4 406.34 ;
    END
  END push_block_i[377]
  PIN push_block_i[378]
    DIRECTION INPUT ;
    USE SIGNAL ;
    PORT
      LAYER Metal3 ;
        RECT  0 404.26 0.4 404.66 ;
    END
  END push_block_i[378]
  PIN push_block_i[379]
    DIRECTION INPUT ;
    USE SIGNAL ;
    PORT
      LAYER Metal3 ;
        RECT  0 402.58 0.4 402.98 ;
    END
  END push_block_i[379]
  PIN push_block_i[37]
    DIRECTION INPUT ;
    USE SIGNAL ;
    PORT
      LAYER Metal3 ;
        RECT  0 977.14 0.4 977.54 ;
    END
  END push_block_i[37]
  PIN push_block_i[380]
    DIRECTION INPUT ;
    USE SIGNAL ;
    PORT
      LAYER Metal3 ;
        RECT  0 400.9 0.4 401.3 ;
    END
  END push_block_i[380]
  PIN push_block_i[381]
    DIRECTION INPUT ;
    USE SIGNAL ;
    PORT
      LAYER Metal3 ;
        RECT  0 399.22 0.4 399.62 ;
    END
  END push_block_i[381]
  PIN push_block_i[382]
    DIRECTION INPUT ;
    USE SIGNAL ;
    PORT
      LAYER Metal3 ;
        RECT  0 397.54 0.4 397.94 ;
    END
  END push_block_i[382]
  PIN push_block_i[383]
    DIRECTION INPUT ;
    USE SIGNAL ;
    PORT
      LAYER Metal3 ;
        RECT  0 395.86 0.4 396.26 ;
    END
  END push_block_i[383]
  PIN push_block_i[384]
    DIRECTION INPUT ;
    USE SIGNAL ;
    PORT
      LAYER Metal3 ;
        RECT  0 394.18 0.4 394.58 ;
    END
  END push_block_i[384]
  PIN push_block_i[385]
    DIRECTION INPUT ;
    USE SIGNAL ;
    PORT
      LAYER Metal3 ;
        RECT  0 392.5 0.4 392.9 ;
    END
  END push_block_i[385]
  PIN push_block_i[386]
    DIRECTION INPUT ;
    USE SIGNAL ;
    PORT
      LAYER Metal3 ;
        RECT  0 390.82 0.4 391.22 ;
    END
  END push_block_i[386]
  PIN push_block_i[387]
    DIRECTION INPUT ;
    USE SIGNAL ;
    PORT
      LAYER Metal3 ;
        RECT  0 389.14 0.4 389.54 ;
    END
  END push_block_i[387]
  PIN push_block_i[388]
    DIRECTION INPUT ;
    USE SIGNAL ;
    PORT
      LAYER Metal3 ;
        RECT  0 387.46 0.4 387.86 ;
    END
  END push_block_i[388]
  PIN push_block_i[389]
    DIRECTION INPUT ;
    USE SIGNAL ;
    PORT
      LAYER Metal3 ;
        RECT  0 385.78 0.4 386.18 ;
    END
  END push_block_i[389]
  PIN push_block_i[38]
    DIRECTION INPUT ;
    USE SIGNAL ;
    PORT
      LAYER Metal3 ;
        RECT  0 975.46 0.4 975.86 ;
    END
  END push_block_i[38]
  PIN push_block_i[390]
    DIRECTION INPUT ;
    USE SIGNAL ;
    PORT
      LAYER Metal3 ;
        RECT  0 384.1 0.4 384.5 ;
    END
  END push_block_i[390]
  PIN push_block_i[391]
    DIRECTION INPUT ;
    USE SIGNAL ;
    PORT
      LAYER Metal3 ;
        RECT  0 382.42 0.4 382.82 ;
    END
  END push_block_i[391]
  PIN push_block_i[392]
    DIRECTION INPUT ;
    USE SIGNAL ;
    PORT
      LAYER Metal3 ;
        RECT  0 380.74 0.4 381.14 ;
    END
  END push_block_i[392]
  PIN push_block_i[393]
    DIRECTION INPUT ;
    USE SIGNAL ;
    PORT
      LAYER Metal3 ;
        RECT  0 379.06 0.4 379.46 ;
    END
  END push_block_i[393]
  PIN push_block_i[394]
    DIRECTION INPUT ;
    USE SIGNAL ;
    PORT
      LAYER Metal3 ;
        RECT  0 377.38 0.4 377.78 ;
    END
  END push_block_i[394]
  PIN push_block_i[395]
    DIRECTION INPUT ;
    USE SIGNAL ;
    PORT
      LAYER Metal3 ;
        RECT  0 375.7 0.4 376.1 ;
    END
  END push_block_i[395]
  PIN push_block_i[396]
    DIRECTION INPUT ;
    USE SIGNAL ;
    PORT
      LAYER Metal3 ;
        RECT  0 374.02 0.4 374.42 ;
    END
  END push_block_i[396]
  PIN push_block_i[397]
    DIRECTION INPUT ;
    USE SIGNAL ;
    PORT
      LAYER Metal3 ;
        RECT  0 372.34 0.4 372.74 ;
    END
  END push_block_i[397]
  PIN push_block_i[398]
    DIRECTION INPUT ;
    USE SIGNAL ;
    PORT
      LAYER Metal3 ;
        RECT  0 370.66 0.4 371.06 ;
    END
  END push_block_i[398]
  PIN push_block_i[399]
    DIRECTION INPUT ;
    USE SIGNAL ;
    PORT
      LAYER Metal3 ;
        RECT  0 368.98 0.4 369.38 ;
    END
  END push_block_i[399]
  PIN push_block_i[39]
    DIRECTION INPUT ;
    USE SIGNAL ;
    PORT
      LAYER Metal3 ;
        RECT  0 973.78 0.4 974.18 ;
    END
  END push_block_i[39]
  PIN push_block_i[3]
    DIRECTION INPUT ;
    USE SIGNAL ;
    PORT
      LAYER Metal3 ;
        RECT  0 1034.26 0.4 1034.66 ;
    END
  END push_block_i[3]
  PIN push_block_i[400]
    DIRECTION INPUT ;
    USE SIGNAL ;
    PORT
      LAYER Metal3 ;
        RECT  0 367.3 0.4 367.7 ;
    END
  END push_block_i[400]
  PIN push_block_i[401]
    DIRECTION INPUT ;
    USE SIGNAL ;
    PORT
      LAYER Metal3 ;
        RECT  0 365.62 0.4 366.02 ;
    END
  END push_block_i[401]
  PIN push_block_i[402]
    DIRECTION INPUT ;
    USE SIGNAL ;
    PORT
      LAYER Metal3 ;
        RECT  0 363.94 0.4 364.34 ;
    END
  END push_block_i[402]
  PIN push_block_i[403]
    DIRECTION INPUT ;
    USE SIGNAL ;
    PORT
      LAYER Metal3 ;
        RECT  0 362.26 0.4 362.66 ;
    END
  END push_block_i[403]
  PIN push_block_i[404]
    DIRECTION INPUT ;
    USE SIGNAL ;
    PORT
      LAYER Metal3 ;
        RECT  0 360.58 0.4 360.98 ;
    END
  END push_block_i[404]
  PIN push_block_i[405]
    DIRECTION INPUT ;
    USE SIGNAL ;
    PORT
      LAYER Metal3 ;
        RECT  0 358.9 0.4 359.3 ;
    END
  END push_block_i[405]
  PIN push_block_i[406]
    DIRECTION INPUT ;
    USE SIGNAL ;
    PORT
      LAYER Metal3 ;
        RECT  0 357.22 0.4 357.62 ;
    END
  END push_block_i[406]
  PIN push_block_i[407]
    DIRECTION INPUT ;
    USE SIGNAL ;
    PORT
      LAYER Metal3 ;
        RECT  0 355.54 0.4 355.94 ;
    END
  END push_block_i[407]
  PIN push_block_i[408]
    DIRECTION INPUT ;
    USE SIGNAL ;
    PORT
      LAYER Metal3 ;
        RECT  0 353.86 0.4 354.26 ;
    END
  END push_block_i[408]
  PIN push_block_i[409]
    DIRECTION INPUT ;
    USE SIGNAL ;
    PORT
      LAYER Metal3 ;
        RECT  0 352.18 0.4 352.58 ;
    END
  END push_block_i[409]
  PIN push_block_i[40]
    DIRECTION INPUT ;
    USE SIGNAL ;
    PORT
      LAYER Metal3 ;
        RECT  0 972.1 0.4 972.5 ;
    END
  END push_block_i[40]
  PIN push_block_i[410]
    DIRECTION INPUT ;
    USE SIGNAL ;
    PORT
      LAYER Metal3 ;
        RECT  0 350.5 0.4 350.9 ;
    END
  END push_block_i[410]
  PIN push_block_i[411]
    DIRECTION INPUT ;
    USE SIGNAL ;
    PORT
      LAYER Metal3 ;
        RECT  0 348.82 0.4 349.22 ;
    END
  END push_block_i[411]
  PIN push_block_i[412]
    DIRECTION INPUT ;
    USE SIGNAL ;
    PORT
      LAYER Metal3 ;
        RECT  0 347.14 0.4 347.54 ;
    END
  END push_block_i[412]
  PIN push_block_i[413]
    DIRECTION INPUT ;
    USE SIGNAL ;
    PORT
      LAYER Metal3 ;
        RECT  0 345.46 0.4 345.86 ;
    END
  END push_block_i[413]
  PIN push_block_i[414]
    DIRECTION INPUT ;
    USE SIGNAL ;
    PORT
      LAYER Metal3 ;
        RECT  0 343.78 0.4 344.18 ;
    END
  END push_block_i[414]
  PIN push_block_i[415]
    DIRECTION INPUT ;
    USE SIGNAL ;
    PORT
      LAYER Metal3 ;
        RECT  0 342.1 0.4 342.5 ;
    END
  END push_block_i[415]
  PIN push_block_i[416]
    DIRECTION INPUT ;
    USE SIGNAL ;
    PORT
      LAYER Metal3 ;
        RECT  0 340.42 0.4 340.82 ;
    END
  END push_block_i[416]
  PIN push_block_i[417]
    DIRECTION INPUT ;
    USE SIGNAL ;
    PORT
      LAYER Metal3 ;
        RECT  0 338.74 0.4 339.14 ;
    END
  END push_block_i[417]
  PIN push_block_i[418]
    DIRECTION INPUT ;
    USE SIGNAL ;
    PORT
      LAYER Metal3 ;
        RECT  0 337.06 0.4 337.46 ;
    END
  END push_block_i[418]
  PIN push_block_i[419]
    DIRECTION INPUT ;
    USE SIGNAL ;
    PORT
      LAYER Metal3 ;
        RECT  0 335.38 0.4 335.78 ;
    END
  END push_block_i[419]
  PIN push_block_i[41]
    DIRECTION INPUT ;
    USE SIGNAL ;
    PORT
      LAYER Metal3 ;
        RECT  0 970.42 0.4 970.82 ;
    END
  END push_block_i[41]
  PIN push_block_i[420]
    DIRECTION INPUT ;
    USE SIGNAL ;
    PORT
      LAYER Metal3 ;
        RECT  0 333.7 0.4 334.1 ;
    END
  END push_block_i[420]
  PIN push_block_i[421]
    DIRECTION INPUT ;
    USE SIGNAL ;
    PORT
      LAYER Metal3 ;
        RECT  0 332.02 0.4 332.42 ;
    END
  END push_block_i[421]
  PIN push_block_i[422]
    DIRECTION INPUT ;
    USE SIGNAL ;
    PORT
      LAYER Metal3 ;
        RECT  0 330.34 0.4 330.74 ;
    END
  END push_block_i[422]
  PIN push_block_i[423]
    DIRECTION INPUT ;
    USE SIGNAL ;
    PORT
      LAYER Metal3 ;
        RECT  0 328.66 0.4 329.06 ;
    END
  END push_block_i[423]
  PIN push_block_i[424]
    DIRECTION INPUT ;
    USE SIGNAL ;
    PORT
      LAYER Metal3 ;
        RECT  0 326.98 0.4 327.38 ;
    END
  END push_block_i[424]
  PIN push_block_i[425]
    DIRECTION INPUT ;
    USE SIGNAL ;
    PORT
      LAYER Metal3 ;
        RECT  0 325.3 0.4 325.7 ;
    END
  END push_block_i[425]
  PIN push_block_i[426]
    DIRECTION INPUT ;
    USE SIGNAL ;
    PORT
      LAYER Metal3 ;
        RECT  0 323.62 0.4 324.02 ;
    END
  END push_block_i[426]
  PIN push_block_i[427]
    DIRECTION INPUT ;
    USE SIGNAL ;
    PORT
      LAYER Metal3 ;
        RECT  0 321.94 0.4 322.34 ;
    END
  END push_block_i[427]
  PIN push_block_i[428]
    DIRECTION INPUT ;
    USE SIGNAL ;
    PORT
      LAYER Metal3 ;
        RECT  0 320.26 0.4 320.66 ;
    END
  END push_block_i[428]
  PIN push_block_i[429]
    DIRECTION INPUT ;
    USE SIGNAL ;
    PORT
      LAYER Metal3 ;
        RECT  0 318.58 0.4 318.98 ;
    END
  END push_block_i[429]
  PIN push_block_i[42]
    DIRECTION INPUT ;
    USE SIGNAL ;
    PORT
      LAYER Metal3 ;
        RECT  0 968.74 0.4 969.14 ;
    END
  END push_block_i[42]
  PIN push_block_i[430]
    DIRECTION INPUT ;
    USE SIGNAL ;
    PORT
      LAYER Metal3 ;
        RECT  0 316.9 0.4 317.3 ;
    END
  END push_block_i[430]
  PIN push_block_i[431]
    DIRECTION INPUT ;
    USE SIGNAL ;
    PORT
      LAYER Metal3 ;
        RECT  0 315.22 0.4 315.62 ;
    END
  END push_block_i[431]
  PIN push_block_i[432]
    DIRECTION INPUT ;
    USE SIGNAL ;
    PORT
      LAYER Metal3 ;
        RECT  0 313.54 0.4 313.94 ;
    END
  END push_block_i[432]
  PIN push_block_i[433]
    DIRECTION INPUT ;
    USE SIGNAL ;
    PORT
      LAYER Metal3 ;
        RECT  0 311.86 0.4 312.26 ;
    END
  END push_block_i[433]
  PIN push_block_i[434]
    DIRECTION INPUT ;
    USE SIGNAL ;
    PORT
      LAYER Metal3 ;
        RECT  0 310.18 0.4 310.58 ;
    END
  END push_block_i[434]
  PIN push_block_i[435]
    DIRECTION INPUT ;
    USE SIGNAL ;
    PORT
      LAYER Metal3 ;
        RECT  0 308.5 0.4 308.9 ;
    END
  END push_block_i[435]
  PIN push_block_i[436]
    DIRECTION INPUT ;
    USE SIGNAL ;
    PORT
      LAYER Metal3 ;
        RECT  0 306.82 0.4 307.22 ;
    END
  END push_block_i[436]
  PIN push_block_i[437]
    DIRECTION INPUT ;
    USE SIGNAL ;
    PORT
      LAYER Metal3 ;
        RECT  0 305.14 0.4 305.54 ;
    END
  END push_block_i[437]
  PIN push_block_i[438]
    DIRECTION INPUT ;
    USE SIGNAL ;
    PORT
      LAYER Metal3 ;
        RECT  0 303.46 0.4 303.86 ;
    END
  END push_block_i[438]
  PIN push_block_i[439]
    DIRECTION INPUT ;
    USE SIGNAL ;
    PORT
      LAYER Metal3 ;
        RECT  0 301.78 0.4 302.18 ;
    END
  END push_block_i[439]
  PIN push_block_i[43]
    DIRECTION INPUT ;
    USE SIGNAL ;
    PORT
      LAYER Metal3 ;
        RECT  0 967.06 0.4 967.46 ;
    END
  END push_block_i[43]
  PIN push_block_i[440]
    DIRECTION INPUT ;
    USE SIGNAL ;
    PORT
      LAYER Metal3 ;
        RECT  0 300.1 0.4 300.5 ;
    END
  END push_block_i[440]
  PIN push_block_i[441]
    DIRECTION INPUT ;
    USE SIGNAL ;
    PORT
      LAYER Metal3 ;
        RECT  0 298.42 0.4 298.82 ;
    END
  END push_block_i[441]
  PIN push_block_i[442]
    DIRECTION INPUT ;
    USE SIGNAL ;
    PORT
      LAYER Metal3 ;
        RECT  0 296.74 0.4 297.14 ;
    END
  END push_block_i[442]
  PIN push_block_i[443]
    DIRECTION INPUT ;
    USE SIGNAL ;
    PORT
      LAYER Metal3 ;
        RECT  0 295.06 0.4 295.46 ;
    END
  END push_block_i[443]
  PIN push_block_i[444]
    DIRECTION INPUT ;
    USE SIGNAL ;
    PORT
      LAYER Metal3 ;
        RECT  0 293.38 0.4 293.78 ;
    END
  END push_block_i[444]
  PIN push_block_i[445]
    DIRECTION INPUT ;
    USE SIGNAL ;
    PORT
      LAYER Metal3 ;
        RECT  0 291.7 0.4 292.1 ;
    END
  END push_block_i[445]
  PIN push_block_i[446]
    DIRECTION INPUT ;
    USE SIGNAL ;
    PORT
      LAYER Metal3 ;
        RECT  0 290.02 0.4 290.42 ;
    END
  END push_block_i[446]
  PIN push_block_i[447]
    DIRECTION INPUT ;
    USE SIGNAL ;
    PORT
      LAYER Metal3 ;
        RECT  0 288.34 0.4 288.74 ;
    END
  END push_block_i[447]
  PIN push_block_i[448]
    DIRECTION INPUT ;
    USE SIGNAL ;
    PORT
      LAYER Metal3 ;
        RECT  0 286.66 0.4 287.06 ;
    END
  END push_block_i[448]
  PIN push_block_i[449]
    DIRECTION INPUT ;
    USE SIGNAL ;
    PORT
      LAYER Metal3 ;
        RECT  0 284.98 0.4 285.38 ;
    END
  END push_block_i[449]
  PIN push_block_i[44]
    DIRECTION INPUT ;
    USE SIGNAL ;
    PORT
      LAYER Metal3 ;
        RECT  0 965.38 0.4 965.78 ;
    END
  END push_block_i[44]
  PIN push_block_i[450]
    DIRECTION INPUT ;
    USE SIGNAL ;
    PORT
      LAYER Metal3 ;
        RECT  0 283.3 0.4 283.7 ;
    END
  END push_block_i[450]
  PIN push_block_i[451]
    DIRECTION INPUT ;
    USE SIGNAL ;
    PORT
      LAYER Metal3 ;
        RECT  0 281.62 0.4 282.02 ;
    END
  END push_block_i[451]
  PIN push_block_i[452]
    DIRECTION INPUT ;
    USE SIGNAL ;
    PORT
      LAYER Metal3 ;
        RECT  0 279.94 0.4 280.34 ;
    END
  END push_block_i[452]
  PIN push_block_i[453]
    DIRECTION INPUT ;
    USE SIGNAL ;
    PORT
      LAYER Metal3 ;
        RECT  0 278.26 0.4 278.66 ;
    END
  END push_block_i[453]
  PIN push_block_i[454]
    DIRECTION INPUT ;
    USE SIGNAL ;
    PORT
      LAYER Metal3 ;
        RECT  0 276.58 0.4 276.98 ;
    END
  END push_block_i[454]
  PIN push_block_i[455]
    DIRECTION INPUT ;
    USE SIGNAL ;
    PORT
      LAYER Metal3 ;
        RECT  0 274.9 0.4 275.3 ;
    END
  END push_block_i[455]
  PIN push_block_i[456]
    DIRECTION INPUT ;
    USE SIGNAL ;
    PORT
      LAYER Metal3 ;
        RECT  0 273.22 0.4 273.62 ;
    END
  END push_block_i[456]
  PIN push_block_i[457]
    DIRECTION INPUT ;
    USE SIGNAL ;
    PORT
      LAYER Metal3 ;
        RECT  0 271.54 0.4 271.94 ;
    END
  END push_block_i[457]
  PIN push_block_i[458]
    DIRECTION INPUT ;
    USE SIGNAL ;
    PORT
      LAYER Metal3 ;
        RECT  0 269.86 0.4 270.26 ;
    END
  END push_block_i[458]
  PIN push_block_i[459]
    DIRECTION INPUT ;
    USE SIGNAL ;
    PORT
      LAYER Metal3 ;
        RECT  0 268.18 0.4 268.58 ;
    END
  END push_block_i[459]
  PIN push_block_i[45]
    DIRECTION INPUT ;
    USE SIGNAL ;
    PORT
      LAYER Metal3 ;
        RECT  0 963.7 0.4 964.1 ;
    END
  END push_block_i[45]
  PIN push_block_i[460]
    DIRECTION INPUT ;
    USE SIGNAL ;
    PORT
      LAYER Metal3 ;
        RECT  0 266.5 0.4 266.9 ;
    END
  END push_block_i[460]
  PIN push_block_i[461]
    DIRECTION INPUT ;
    USE SIGNAL ;
    PORT
      LAYER Metal3 ;
        RECT  0 264.82 0.4 265.22 ;
    END
  END push_block_i[461]
  PIN push_block_i[462]
    DIRECTION INPUT ;
    USE SIGNAL ;
    PORT
      LAYER Metal3 ;
        RECT  0 263.14 0.4 263.54 ;
    END
  END push_block_i[462]
  PIN push_block_i[463]
    DIRECTION INPUT ;
    USE SIGNAL ;
    PORT
      LAYER Metal3 ;
        RECT  0 261.46 0.4 261.86 ;
    END
  END push_block_i[463]
  PIN push_block_i[464]
    DIRECTION INPUT ;
    USE SIGNAL ;
    PORT
      LAYER Metal3 ;
        RECT  0 259.78 0.4 260.18 ;
    END
  END push_block_i[464]
  PIN push_block_i[465]
    DIRECTION INPUT ;
    USE SIGNAL ;
    PORT
      LAYER Metal3 ;
        RECT  0 258.1 0.4 258.5 ;
    END
  END push_block_i[465]
  PIN push_block_i[466]
    DIRECTION INPUT ;
    USE SIGNAL ;
    PORT
      LAYER Metal3 ;
        RECT  0 256.42 0.4 256.82 ;
    END
  END push_block_i[466]
  PIN push_block_i[467]
    DIRECTION INPUT ;
    USE SIGNAL ;
    PORT
      LAYER Metal3 ;
        RECT  0 254.74 0.4 255.14 ;
    END
  END push_block_i[467]
  PIN push_block_i[468]
    DIRECTION INPUT ;
    USE SIGNAL ;
    PORT
      LAYER Metal3 ;
        RECT  0 253.06 0.4 253.46 ;
    END
  END push_block_i[468]
  PIN push_block_i[469]
    DIRECTION INPUT ;
    USE SIGNAL ;
    PORT
      LAYER Metal3 ;
        RECT  0 251.38 0.4 251.78 ;
    END
  END push_block_i[469]
  PIN push_block_i[46]
    DIRECTION INPUT ;
    USE SIGNAL ;
    PORT
      LAYER Metal3 ;
        RECT  0 962.02 0.4 962.42 ;
    END
  END push_block_i[46]
  PIN push_block_i[470]
    DIRECTION INPUT ;
    USE SIGNAL ;
    PORT
      LAYER Metal3 ;
        RECT  0 249.7 0.4 250.1 ;
    END
  END push_block_i[470]
  PIN push_block_i[471]
    DIRECTION INPUT ;
    USE SIGNAL ;
    PORT
      LAYER Metal3 ;
        RECT  0 248.02 0.4 248.42 ;
    END
  END push_block_i[471]
  PIN push_block_i[472]
    DIRECTION INPUT ;
    USE SIGNAL ;
    PORT
      LAYER Metal3 ;
        RECT  0 246.34 0.4 246.74 ;
    END
  END push_block_i[472]
  PIN push_block_i[473]
    DIRECTION INPUT ;
    USE SIGNAL ;
    PORT
      LAYER Metal3 ;
        RECT  0 244.66 0.4 245.06 ;
    END
  END push_block_i[473]
  PIN push_block_i[474]
    DIRECTION INPUT ;
    USE SIGNAL ;
    PORT
      LAYER Metal3 ;
        RECT  0 242.98 0.4 243.38 ;
    END
  END push_block_i[474]
  PIN push_block_i[475]
    DIRECTION INPUT ;
    USE SIGNAL ;
    PORT
      LAYER Metal3 ;
        RECT  0 241.3 0.4 241.7 ;
    END
  END push_block_i[475]
  PIN push_block_i[476]
    DIRECTION INPUT ;
    USE SIGNAL ;
    PORT
      LAYER Metal3 ;
        RECT  0 239.62 0.4 240.02 ;
    END
  END push_block_i[476]
  PIN push_block_i[477]
    DIRECTION INPUT ;
    USE SIGNAL ;
    PORT
      LAYER Metal3 ;
        RECT  0 237.94 0.4 238.34 ;
    END
  END push_block_i[477]
  PIN push_block_i[478]
    DIRECTION INPUT ;
    USE SIGNAL ;
    PORT
      LAYER Metal3 ;
        RECT  0 236.26 0.4 236.66 ;
    END
  END push_block_i[478]
  PIN push_block_i[479]
    DIRECTION INPUT ;
    USE SIGNAL ;
    PORT
      LAYER Metal3 ;
        RECT  0 234.58 0.4 234.98 ;
    END
  END push_block_i[479]
  PIN push_block_i[47]
    DIRECTION INPUT ;
    USE SIGNAL ;
    PORT
      LAYER Metal3 ;
        RECT  0 960.34 0.4 960.74 ;
    END
  END push_block_i[47]
  PIN push_block_i[480]
    DIRECTION INPUT ;
    USE SIGNAL ;
    PORT
      LAYER Metal3 ;
        RECT  0 232.9 0.4 233.3 ;
    END
  END push_block_i[480]
  PIN push_block_i[481]
    DIRECTION INPUT ;
    USE SIGNAL ;
    PORT
      LAYER Metal3 ;
        RECT  0 231.22 0.4 231.62 ;
    END
  END push_block_i[481]
  PIN push_block_i[482]
    DIRECTION INPUT ;
    USE SIGNAL ;
    PORT
      LAYER Metal3 ;
        RECT  0 229.54 0.4 229.94 ;
    END
  END push_block_i[482]
  PIN push_block_i[483]
    DIRECTION INPUT ;
    USE SIGNAL ;
    PORT
      LAYER Metal3 ;
        RECT  0 227.86 0.4 228.26 ;
    END
  END push_block_i[483]
  PIN push_block_i[484]
    DIRECTION INPUT ;
    USE SIGNAL ;
    PORT
      LAYER Metal3 ;
        RECT  0 226.18 0.4 226.58 ;
    END
  END push_block_i[484]
  PIN push_block_i[485]
    DIRECTION INPUT ;
    USE SIGNAL ;
    PORT
      LAYER Metal3 ;
        RECT  0 224.5 0.4 224.9 ;
    END
  END push_block_i[485]
  PIN push_block_i[486]
    DIRECTION INPUT ;
    USE SIGNAL ;
    PORT
      LAYER Metal3 ;
        RECT  0 222.82 0.4 223.22 ;
    END
  END push_block_i[486]
  PIN push_block_i[487]
    DIRECTION INPUT ;
    USE SIGNAL ;
    PORT
      LAYER Metal3 ;
        RECT  0 221.14 0.4 221.54 ;
    END
  END push_block_i[487]
  PIN push_block_i[488]
    DIRECTION INPUT ;
    USE SIGNAL ;
    PORT
      LAYER Metal3 ;
        RECT  0 219.46 0.4 219.86 ;
    END
  END push_block_i[488]
  PIN push_block_i[489]
    DIRECTION INPUT ;
    USE SIGNAL ;
    PORT
      LAYER Metal3 ;
        RECT  0 217.78 0.4 218.18 ;
    END
  END push_block_i[489]
  PIN push_block_i[48]
    DIRECTION INPUT ;
    USE SIGNAL ;
    PORT
      LAYER Metal3 ;
        RECT  0 958.66 0.4 959.06 ;
    END
  END push_block_i[48]
  PIN push_block_i[490]
    DIRECTION INPUT ;
    USE SIGNAL ;
    PORT
      LAYER Metal3 ;
        RECT  0 216.1 0.4 216.5 ;
    END
  END push_block_i[490]
  PIN push_block_i[491]
    DIRECTION INPUT ;
    USE SIGNAL ;
    PORT
      LAYER Metal3 ;
        RECT  0 214.42 0.4 214.82 ;
    END
  END push_block_i[491]
  PIN push_block_i[492]
    DIRECTION INPUT ;
    USE SIGNAL ;
    PORT
      LAYER Metal3 ;
        RECT  0 212.74 0.4 213.14 ;
    END
  END push_block_i[492]
  PIN push_block_i[493]
    DIRECTION INPUT ;
    USE SIGNAL ;
    PORT
      LAYER Metal3 ;
        RECT  0 211.06 0.4 211.46 ;
    END
  END push_block_i[493]
  PIN push_block_i[494]
    DIRECTION INPUT ;
    USE SIGNAL ;
    PORT
      LAYER Metal3 ;
        RECT  0 209.38 0.4 209.78 ;
    END
  END push_block_i[494]
  PIN push_block_i[495]
    DIRECTION INPUT ;
    USE SIGNAL ;
    PORT
      LAYER Metal3 ;
        RECT  0 207.7 0.4 208.1 ;
    END
  END push_block_i[495]
  PIN push_block_i[496]
    DIRECTION INPUT ;
    USE SIGNAL ;
    PORT
      LAYER Metal3 ;
        RECT  0 206.02 0.4 206.42 ;
    END
  END push_block_i[496]
  PIN push_block_i[497]
    DIRECTION INPUT ;
    USE SIGNAL ;
    PORT
      LAYER Metal3 ;
        RECT  0 204.34 0.4 204.74 ;
    END
  END push_block_i[497]
  PIN push_block_i[498]
    DIRECTION INPUT ;
    USE SIGNAL ;
    PORT
      LAYER Metal3 ;
        RECT  0 202.66 0.4 203.06 ;
    END
  END push_block_i[498]
  PIN push_block_i[499]
    DIRECTION INPUT ;
    USE SIGNAL ;
    PORT
      LAYER Metal3 ;
        RECT  0 200.98 0.4 201.38 ;
    END
  END push_block_i[499]
  PIN push_block_i[49]
    DIRECTION INPUT ;
    USE SIGNAL ;
    PORT
      LAYER Metal3 ;
        RECT  0 956.98 0.4 957.38 ;
    END
  END push_block_i[49]
  PIN push_block_i[4]
    DIRECTION INPUT ;
    USE SIGNAL ;
    PORT
      LAYER Metal3 ;
        RECT  0 1032.58 0.4 1032.98 ;
    END
  END push_block_i[4]
  PIN push_block_i[500]
    DIRECTION INPUT ;
    USE SIGNAL ;
    PORT
      LAYER Metal3 ;
        RECT  0 199.3 0.4 199.7 ;
    END
  END push_block_i[500]
  PIN push_block_i[501]
    DIRECTION INPUT ;
    USE SIGNAL ;
    PORT
      LAYER Metal3 ;
        RECT  0 197.62 0.4 198.02 ;
    END
  END push_block_i[501]
  PIN push_block_i[502]
    DIRECTION INPUT ;
    USE SIGNAL ;
    PORT
      LAYER Metal3 ;
        RECT  0 195.94 0.4 196.34 ;
    END
  END push_block_i[502]
  PIN push_block_i[503]
    DIRECTION INPUT ;
    USE SIGNAL ;
    PORT
      LAYER Metal3 ;
        RECT  0 194.26 0.4 194.66 ;
    END
  END push_block_i[503]
  PIN push_block_i[504]
    DIRECTION INPUT ;
    USE SIGNAL ;
    PORT
      LAYER Metal3 ;
        RECT  0 192.58 0.4 192.98 ;
    END
  END push_block_i[504]
  PIN push_block_i[505]
    DIRECTION INPUT ;
    USE SIGNAL ;
    PORT
      LAYER Metal3 ;
        RECT  0 190.9 0.4 191.3 ;
    END
  END push_block_i[505]
  PIN push_block_i[506]
    DIRECTION INPUT ;
    USE SIGNAL ;
    PORT
      LAYER Metal3 ;
        RECT  0 189.22 0.4 189.62 ;
    END
  END push_block_i[506]
  PIN push_block_i[507]
    DIRECTION INPUT ;
    USE SIGNAL ;
    PORT
      LAYER Metal3 ;
        RECT  0 187.54 0.4 187.94 ;
    END
  END push_block_i[507]
  PIN push_block_i[508]
    DIRECTION INPUT ;
    USE SIGNAL ;
    PORT
      LAYER Metal3 ;
        RECT  0 185.86 0.4 186.26 ;
    END
  END push_block_i[508]
  PIN push_block_i[509]
    DIRECTION INPUT ;
    USE SIGNAL ;
    PORT
      LAYER Metal3 ;
        RECT  0 184.18 0.4 184.58 ;
    END
  END push_block_i[509]
  PIN push_block_i[50]
    DIRECTION INPUT ;
    USE SIGNAL ;
    PORT
      LAYER Metal3 ;
        RECT  0 955.3 0.4 955.7 ;
    END
  END push_block_i[50]
  PIN push_block_i[510]
    DIRECTION INPUT ;
    USE SIGNAL ;
    PORT
      LAYER Metal3 ;
        RECT  0 182.5 0.4 182.9 ;
    END
  END push_block_i[510]
  PIN push_block_i[511]
    DIRECTION INPUT ;
    USE SIGNAL ;
    PORT
      LAYER Metal3 ;
        RECT  0 180.82 0.4 181.22 ;
    END
  END push_block_i[511]
  PIN push_block_i[512]
    DIRECTION INPUT ;
    USE SIGNAL ;
    PORT
      LAYER Metal3 ;
        RECT  0 179.14 0.4 179.54 ;
    END
  END push_block_i[512]
  PIN push_block_i[513]
    DIRECTION INPUT ;
    USE SIGNAL ;
    PORT
      LAYER Metal3 ;
        RECT  0 177.46 0.4 177.86 ;
    END
  END push_block_i[513]
  PIN push_block_i[514]
    DIRECTION INPUT ;
    USE SIGNAL ;
    PORT
      LAYER Metal3 ;
        RECT  0 175.78 0.4 176.18 ;
    END
  END push_block_i[514]
  PIN push_block_i[515]
    DIRECTION INPUT ;
    USE SIGNAL ;
    PORT
      LAYER Metal3 ;
        RECT  0 174.1 0.4 174.5 ;
    END
  END push_block_i[515]
  PIN push_block_i[516]
    DIRECTION INPUT ;
    USE SIGNAL ;
    PORT
      LAYER Metal3 ;
        RECT  0 172.42 0.4 172.82 ;
    END
  END push_block_i[516]
  PIN push_block_i[517]
    DIRECTION INPUT ;
    USE SIGNAL ;
    PORT
      LAYER Metal3 ;
        RECT  0 170.74 0.4 171.14 ;
    END
  END push_block_i[517]
  PIN push_block_i[518]
    DIRECTION INPUT ;
    USE SIGNAL ;
    PORT
      LAYER Metal3 ;
        RECT  0 169.06 0.4 169.46 ;
    END
  END push_block_i[518]
  PIN push_block_i[519]
    DIRECTION INPUT ;
    USE SIGNAL ;
    PORT
      LAYER Metal3 ;
        RECT  0 167.38 0.4 167.78 ;
    END
  END push_block_i[519]
  PIN push_block_i[51]
    DIRECTION INPUT ;
    USE SIGNAL ;
    PORT
      LAYER Metal3 ;
        RECT  0 953.62 0.4 954.02 ;
    END
  END push_block_i[51]
  PIN push_block_i[520]
    DIRECTION INPUT ;
    USE SIGNAL ;
    PORT
      LAYER Metal3 ;
        RECT  0 165.7 0.4 166.1 ;
    END
  END push_block_i[520]
  PIN push_block_i[521]
    DIRECTION INPUT ;
    USE SIGNAL ;
    PORT
      LAYER Metal3 ;
        RECT  0 164.02 0.4 164.42 ;
    END
  END push_block_i[521]
  PIN push_block_i[522]
    DIRECTION INPUT ;
    USE SIGNAL ;
    PORT
      LAYER Metal3 ;
        RECT  0 162.34 0.4 162.74 ;
    END
  END push_block_i[522]
  PIN push_block_i[523]
    DIRECTION INPUT ;
    USE SIGNAL ;
    PORT
      LAYER Metal3 ;
        RECT  0 160.66 0.4 161.06 ;
    END
  END push_block_i[523]
  PIN push_block_i[524]
    DIRECTION INPUT ;
    USE SIGNAL ;
    PORT
      LAYER Metal3 ;
        RECT  0 158.98 0.4 159.38 ;
    END
  END push_block_i[524]
  PIN push_block_i[525]
    DIRECTION INPUT ;
    USE SIGNAL ;
    PORT
      LAYER Metal3 ;
        RECT  0 157.3 0.4 157.7 ;
    END
  END push_block_i[525]
  PIN push_block_i[526]
    DIRECTION INPUT ;
    USE SIGNAL ;
    PORT
      LAYER Metal3 ;
        RECT  0 155.62 0.4 156.02 ;
    END
  END push_block_i[526]
  PIN push_block_i[527]
    DIRECTION INPUT ;
    USE SIGNAL ;
    PORT
      LAYER Metal3 ;
        RECT  0 153.94 0.4 154.34 ;
    END
  END push_block_i[527]
  PIN push_block_i[528]
    DIRECTION INPUT ;
    USE SIGNAL ;
    PORT
      LAYER Metal3 ;
        RECT  0 152.26 0.4 152.66 ;
    END
  END push_block_i[528]
  PIN push_block_i[529]
    DIRECTION INPUT ;
    USE SIGNAL ;
    PORT
      LAYER Metal3 ;
        RECT  0 150.58 0.4 150.98 ;
    END
  END push_block_i[529]
  PIN push_block_i[52]
    DIRECTION INPUT ;
    USE SIGNAL ;
    PORT
      LAYER Metal3 ;
        RECT  0 951.94 0.4 952.34 ;
    END
  END push_block_i[52]
  PIN push_block_i[530]
    DIRECTION INPUT ;
    USE SIGNAL ;
    PORT
      LAYER Metal3 ;
        RECT  0 148.9 0.4 149.3 ;
    END
  END push_block_i[530]
  PIN push_block_i[531]
    DIRECTION INPUT ;
    USE SIGNAL ;
    PORT
      LAYER Metal3 ;
        RECT  0 147.22 0.4 147.62 ;
    END
  END push_block_i[531]
  PIN push_block_i[532]
    DIRECTION INPUT ;
    USE SIGNAL ;
    PORT
      LAYER Metal3 ;
        RECT  0 145.54 0.4 145.94 ;
    END
  END push_block_i[532]
  PIN push_block_i[533]
    DIRECTION INPUT ;
    USE SIGNAL ;
    PORT
      LAYER Metal3 ;
        RECT  0 143.86 0.4 144.26 ;
    END
  END push_block_i[533]
  PIN push_block_i[534]
    DIRECTION INPUT ;
    USE SIGNAL ;
    PORT
      LAYER Metal3 ;
        RECT  0 142.18 0.4 142.58 ;
    END
  END push_block_i[534]
  PIN push_block_i[535]
    DIRECTION INPUT ;
    USE SIGNAL ;
    PORT
      LAYER Metal3 ;
        RECT  0 140.5 0.4 140.9 ;
    END
  END push_block_i[535]
  PIN push_block_i[536]
    DIRECTION INPUT ;
    USE SIGNAL ;
    PORT
      LAYER Metal3 ;
        RECT  0 138.82 0.4 139.22 ;
    END
  END push_block_i[536]
  PIN push_block_i[537]
    DIRECTION INPUT ;
    USE SIGNAL ;
    PORT
      LAYER Metal3 ;
        RECT  0 137.14 0.4 137.54 ;
    END
  END push_block_i[537]
  PIN push_block_i[538]
    DIRECTION INPUT ;
    USE SIGNAL ;
    PORT
      LAYER Metal3 ;
        RECT  0 135.46 0.4 135.86 ;
    END
  END push_block_i[538]
  PIN push_block_i[539]
    DIRECTION INPUT ;
    USE SIGNAL ;
    PORT
      LAYER Metal3 ;
        RECT  0 133.78 0.4 134.18 ;
    END
  END push_block_i[539]
  PIN push_block_i[53]
    DIRECTION INPUT ;
    USE SIGNAL ;
    PORT
      LAYER Metal3 ;
        RECT  0 950.26 0.4 950.66 ;
    END
  END push_block_i[53]
  PIN push_block_i[540]
    DIRECTION INPUT ;
    USE SIGNAL ;
    PORT
      LAYER Metal3 ;
        RECT  0 132.1 0.4 132.5 ;
    END
  END push_block_i[540]
  PIN push_block_i[541]
    DIRECTION INPUT ;
    USE SIGNAL ;
    PORT
      LAYER Metal3 ;
        RECT  0 130.42 0.4 130.82 ;
    END
  END push_block_i[541]
  PIN push_block_i[542]
    DIRECTION INPUT ;
    USE SIGNAL ;
    PORT
      LAYER Metal3 ;
        RECT  0 128.74 0.4 129.14 ;
    END
  END push_block_i[542]
  PIN push_block_i[543]
    DIRECTION INPUT ;
    USE SIGNAL ;
    PORT
      LAYER Metal3 ;
        RECT  0 127.06 0.4 127.46 ;
    END
  END push_block_i[543]
  PIN push_block_i[544]
    DIRECTION INPUT ;
    USE SIGNAL ;
    PORT
      LAYER Metal3 ;
        RECT  0 125.38 0.4 125.78 ;
    END
  END push_block_i[544]
  PIN push_block_i[545]
    DIRECTION INPUT ;
    USE SIGNAL ;
    PORT
      LAYER Metal3 ;
        RECT  0 123.7 0.4 124.1 ;
    END
  END push_block_i[545]
  PIN push_block_i[546]
    DIRECTION INPUT ;
    USE SIGNAL ;
    PORT
      LAYER Metal3 ;
        RECT  0 122.02 0.4 122.42 ;
    END
  END push_block_i[546]
  PIN push_block_i[547]
    DIRECTION INPUT ;
    USE SIGNAL ;
    PORT
      LAYER Metal3 ;
        RECT  0 120.34 0.4 120.74 ;
    END
  END push_block_i[547]
  PIN push_block_i[548]
    DIRECTION INPUT ;
    USE SIGNAL ;
    PORT
      LAYER Metal3 ;
        RECT  0 118.66 0.4 119.06 ;
    END
  END push_block_i[548]
  PIN push_block_i[549]
    DIRECTION INPUT ;
    USE SIGNAL ;
    PORT
      LAYER Metal3 ;
        RECT  0 116.98 0.4 117.38 ;
    END
  END push_block_i[549]
  PIN push_block_i[54]
    DIRECTION INPUT ;
    USE SIGNAL ;
    PORT
      LAYER Metal3 ;
        RECT  0 948.58 0.4 948.98 ;
    END
  END push_block_i[54]
  PIN push_block_i[550]
    DIRECTION INPUT ;
    USE SIGNAL ;
    PORT
      LAYER Metal3 ;
        RECT  0 115.3 0.4 115.7 ;
    END
  END push_block_i[550]
  PIN push_block_i[551]
    DIRECTION INPUT ;
    USE SIGNAL ;
    PORT
      LAYER Metal3 ;
        RECT  0 113.62 0.4 114.02 ;
    END
  END push_block_i[551]
  PIN push_block_i[552]
    DIRECTION INPUT ;
    USE SIGNAL ;
    PORT
      LAYER Metal3 ;
        RECT  0 111.94 0.4 112.34 ;
    END
  END push_block_i[552]
  PIN push_block_i[553]
    DIRECTION INPUT ;
    USE SIGNAL ;
    PORT
      LAYER Metal3 ;
        RECT  0 110.26 0.4 110.66 ;
    END
  END push_block_i[553]
  PIN push_block_i[554]
    DIRECTION INPUT ;
    USE SIGNAL ;
    PORT
      LAYER Metal3 ;
        RECT  0 108.58 0.4 108.98 ;
    END
  END push_block_i[554]
  PIN push_block_i[555]
    DIRECTION INPUT ;
    USE SIGNAL ;
    PORT
      LAYER Metal3 ;
        RECT  0 106.9 0.4 107.3 ;
    END
  END push_block_i[555]
  PIN push_block_i[556]
    DIRECTION INPUT ;
    USE SIGNAL ;
    PORT
      LAYER Metal3 ;
        RECT  0 105.22 0.4 105.62 ;
    END
  END push_block_i[556]
  PIN push_block_i[557]
    DIRECTION INPUT ;
    USE SIGNAL ;
    PORT
      LAYER Metal3 ;
        RECT  0 103.54 0.4 103.94 ;
    END
  END push_block_i[557]
  PIN push_block_i[558]
    DIRECTION INPUT ;
    USE SIGNAL ;
    PORT
      LAYER Metal3 ;
        RECT  0 101.86 0.4 102.26 ;
    END
  END push_block_i[558]
  PIN push_block_i[559]
    DIRECTION INPUT ;
    USE SIGNAL ;
    PORT
      LAYER Metal3 ;
        RECT  0 100.18 0.4 100.58 ;
    END
  END push_block_i[559]
  PIN push_block_i[55]
    DIRECTION INPUT ;
    USE SIGNAL ;
    PORT
      LAYER Metal3 ;
        RECT  0 946.9 0.4 947.3 ;
    END
  END push_block_i[55]
  PIN push_block_i[560]
    DIRECTION INPUT ;
    USE SIGNAL ;
    PORT
      LAYER Metal3 ;
        RECT  0 98.5 0.4 98.9 ;
    END
  END push_block_i[560]
  PIN push_block_i[561]
    DIRECTION INPUT ;
    USE SIGNAL ;
    PORT
      LAYER Metal3 ;
        RECT  0 96.82 0.4 97.22 ;
    END
  END push_block_i[561]
  PIN push_block_i[562]
    DIRECTION INPUT ;
    USE SIGNAL ;
    PORT
      LAYER Metal3 ;
        RECT  0 95.14 0.4 95.54 ;
    END
  END push_block_i[562]
  PIN push_block_i[563]
    DIRECTION INPUT ;
    USE SIGNAL ;
    PORT
      LAYER Metal3 ;
        RECT  0 93.46 0.4 93.86 ;
    END
  END push_block_i[563]
  PIN push_block_i[564]
    DIRECTION INPUT ;
    USE SIGNAL ;
    PORT
      LAYER Metal3 ;
        RECT  0 91.78 0.4 92.18 ;
    END
  END push_block_i[564]
  PIN push_block_i[565]
    DIRECTION INPUT ;
    USE SIGNAL ;
    PORT
      LAYER Metal3 ;
        RECT  0 90.1 0.4 90.5 ;
    END
  END push_block_i[565]
  PIN push_block_i[566]
    DIRECTION INPUT ;
    USE SIGNAL ;
    PORT
      LAYER Metal3 ;
        RECT  0 88.42 0.4 88.82 ;
    END
  END push_block_i[566]
  PIN push_block_i[567]
    DIRECTION INPUT ;
    USE SIGNAL ;
    PORT
      LAYER Metal3 ;
        RECT  0 86.74 0.4 87.14 ;
    END
  END push_block_i[567]
  PIN push_block_i[568]
    DIRECTION INPUT ;
    USE SIGNAL ;
    PORT
      LAYER Metal3 ;
        RECT  0 85.06 0.4 85.46 ;
    END
  END push_block_i[568]
  PIN push_block_i[569]
    DIRECTION INPUT ;
    USE SIGNAL ;
    PORT
      LAYER Metal3 ;
        RECT  0 83.38 0.4 83.78 ;
    END
  END push_block_i[569]
  PIN push_block_i[56]
    DIRECTION INPUT ;
    USE SIGNAL ;
    PORT
      LAYER Metal3 ;
        RECT  0 945.22 0.4 945.62 ;
    END
  END push_block_i[56]
  PIN push_block_i[570]
    DIRECTION INPUT ;
    USE SIGNAL ;
    PORT
      LAYER Metal3 ;
        RECT  0 81.7 0.4 82.1 ;
    END
  END push_block_i[570]
  PIN push_block_i[571]
    DIRECTION INPUT ;
    USE SIGNAL ;
    PORT
      LAYER Metal3 ;
        RECT  0 80.02 0.4 80.42 ;
    END
  END push_block_i[571]
  PIN push_block_i[57]
    DIRECTION INPUT ;
    USE SIGNAL ;
    PORT
      LAYER Metal3 ;
        RECT  0 943.54 0.4 943.94 ;
    END
  END push_block_i[57]
  PIN push_block_i[58]
    DIRECTION INPUT ;
    USE SIGNAL ;
    PORT
      LAYER Metal3 ;
        RECT  0 941.86 0.4 942.26 ;
    END
  END push_block_i[58]
  PIN push_block_i[59]
    DIRECTION INPUT ;
    USE SIGNAL ;
    PORT
      LAYER Metal3 ;
        RECT  0 940.18 0.4 940.58 ;
    END
  END push_block_i[59]
  PIN push_block_i[5]
    DIRECTION INPUT ;
    USE SIGNAL ;
    PORT
      LAYER Metal3 ;
        RECT  0 1030.9 0.4 1031.3 ;
    END
  END push_block_i[5]
  PIN push_block_i[60]
    DIRECTION INPUT ;
    USE SIGNAL ;
    PORT
      LAYER Metal3 ;
        RECT  0 938.5 0.4 938.9 ;
    END
  END push_block_i[60]
  PIN push_block_i[61]
    DIRECTION INPUT ;
    USE SIGNAL ;
    PORT
      LAYER Metal3 ;
        RECT  0 936.82 0.4 937.22 ;
    END
  END push_block_i[61]
  PIN push_block_i[62]
    DIRECTION INPUT ;
    USE SIGNAL ;
    PORT
      LAYER Metal3 ;
        RECT  0 935.14 0.4 935.54 ;
    END
  END push_block_i[62]
  PIN push_block_i[63]
    DIRECTION INPUT ;
    USE SIGNAL ;
    PORT
      LAYER Metal3 ;
        RECT  0 933.46 0.4 933.86 ;
    END
  END push_block_i[63]
  PIN push_block_i[64]
    DIRECTION INPUT ;
    USE SIGNAL ;
    PORT
      LAYER Metal3 ;
        RECT  0 931.78 0.4 932.18 ;
    END
  END push_block_i[64]
  PIN push_block_i[65]
    DIRECTION INPUT ;
    USE SIGNAL ;
    PORT
      LAYER Metal3 ;
        RECT  0 930.1 0.4 930.5 ;
    END
  END push_block_i[65]
  PIN push_block_i[66]
    DIRECTION INPUT ;
    USE SIGNAL ;
    PORT
      LAYER Metal3 ;
        RECT  0 928.42 0.4 928.82 ;
    END
  END push_block_i[66]
  PIN push_block_i[67]
    DIRECTION INPUT ;
    USE SIGNAL ;
    PORT
      LAYER Metal3 ;
        RECT  0 926.74 0.4 927.14 ;
    END
  END push_block_i[67]
  PIN push_block_i[68]
    DIRECTION INPUT ;
    USE SIGNAL ;
    PORT
      LAYER Metal3 ;
        RECT  0 925.06 0.4 925.46 ;
    END
  END push_block_i[68]
  PIN push_block_i[69]
    DIRECTION INPUT ;
    USE SIGNAL ;
    PORT
      LAYER Metal3 ;
        RECT  0 923.38 0.4 923.78 ;
    END
  END push_block_i[69]
  PIN push_block_i[6]
    DIRECTION INPUT ;
    USE SIGNAL ;
    PORT
      LAYER Metal3 ;
        RECT  0 1029.22 0.4 1029.62 ;
    END
  END push_block_i[6]
  PIN push_block_i[70]
    DIRECTION INPUT ;
    USE SIGNAL ;
    PORT
      LAYER Metal3 ;
        RECT  0 921.7 0.4 922.1 ;
    END
  END push_block_i[70]
  PIN push_block_i[71]
    DIRECTION INPUT ;
    USE SIGNAL ;
    PORT
      LAYER Metal3 ;
        RECT  0 920.02 0.4 920.42 ;
    END
  END push_block_i[71]
  PIN push_block_i[72]
    DIRECTION INPUT ;
    USE SIGNAL ;
    PORT
      LAYER Metal3 ;
        RECT  0 918.34 0.4 918.74 ;
    END
  END push_block_i[72]
  PIN push_block_i[73]
    DIRECTION INPUT ;
    USE SIGNAL ;
    PORT
      LAYER Metal3 ;
        RECT  0 916.66 0.4 917.06 ;
    END
  END push_block_i[73]
  PIN push_block_i[74]
    DIRECTION INPUT ;
    USE SIGNAL ;
    PORT
      LAYER Metal3 ;
        RECT  0 914.98 0.4 915.38 ;
    END
  END push_block_i[74]
  PIN push_block_i[75]
    DIRECTION INPUT ;
    USE SIGNAL ;
    PORT
      LAYER Metal3 ;
        RECT  0 913.3 0.4 913.7 ;
    END
  END push_block_i[75]
  PIN push_block_i[76]
    DIRECTION INPUT ;
    USE SIGNAL ;
    PORT
      LAYER Metal3 ;
        RECT  0 911.62 0.4 912.02 ;
    END
  END push_block_i[76]
  PIN push_block_i[77]
    DIRECTION INPUT ;
    USE SIGNAL ;
    PORT
      LAYER Metal3 ;
        RECT  0 909.94 0.4 910.34 ;
    END
  END push_block_i[77]
  PIN push_block_i[78]
    DIRECTION INPUT ;
    USE SIGNAL ;
    PORT
      LAYER Metal3 ;
        RECT  0 908.26 0.4 908.66 ;
    END
  END push_block_i[78]
  PIN push_block_i[79]
    DIRECTION INPUT ;
    USE SIGNAL ;
    PORT
      LAYER Metal3 ;
        RECT  0 906.58 0.4 906.98 ;
    END
  END push_block_i[79]
  PIN push_block_i[7]
    DIRECTION INPUT ;
    USE SIGNAL ;
    PORT
      LAYER Metal3 ;
        RECT  0 1027.54 0.4 1027.94 ;
    END
  END push_block_i[7]
  PIN push_block_i[80]
    DIRECTION INPUT ;
    USE SIGNAL ;
    PORT
      LAYER Metal3 ;
        RECT  0 904.9 0.4 905.3 ;
    END
  END push_block_i[80]
  PIN push_block_i[81]
    DIRECTION INPUT ;
    USE SIGNAL ;
    PORT
      LAYER Metal3 ;
        RECT  0 903.22 0.4 903.62 ;
    END
  END push_block_i[81]
  PIN push_block_i[82]
    DIRECTION INPUT ;
    USE SIGNAL ;
    PORT
      LAYER Metal3 ;
        RECT  0 901.54 0.4 901.94 ;
    END
  END push_block_i[82]
  PIN push_block_i[83]
    DIRECTION INPUT ;
    USE SIGNAL ;
    PORT
      LAYER Metal3 ;
        RECT  0 899.86 0.4 900.26 ;
    END
  END push_block_i[83]
  PIN push_block_i[84]
    DIRECTION INPUT ;
    USE SIGNAL ;
    PORT
      LAYER Metal3 ;
        RECT  0 898.18 0.4 898.58 ;
    END
  END push_block_i[84]
  PIN push_block_i[85]
    DIRECTION INPUT ;
    USE SIGNAL ;
    PORT
      LAYER Metal3 ;
        RECT  0 896.5 0.4 896.9 ;
    END
  END push_block_i[85]
  PIN push_block_i[86]
    DIRECTION INPUT ;
    USE SIGNAL ;
    PORT
      LAYER Metal3 ;
        RECT  0 894.82 0.4 895.22 ;
    END
  END push_block_i[86]
  PIN push_block_i[87]
    DIRECTION INPUT ;
    USE SIGNAL ;
    PORT
      LAYER Metal3 ;
        RECT  0 893.14 0.4 893.54 ;
    END
  END push_block_i[87]
  PIN push_block_i[88]
    DIRECTION INPUT ;
    USE SIGNAL ;
    PORT
      LAYER Metal3 ;
        RECT  0 891.46 0.4 891.86 ;
    END
  END push_block_i[88]
  PIN push_block_i[89]
    DIRECTION INPUT ;
    USE SIGNAL ;
    PORT
      LAYER Metal3 ;
        RECT  0 889.78 0.4 890.18 ;
    END
  END push_block_i[89]
  PIN push_block_i[8]
    DIRECTION INPUT ;
    USE SIGNAL ;
    PORT
      LAYER Metal3 ;
        RECT  0 1025.86 0.4 1026.26 ;
    END
  END push_block_i[8]
  PIN push_block_i[90]
    DIRECTION INPUT ;
    USE SIGNAL ;
    PORT
      LAYER Metal3 ;
        RECT  0 888.1 0.4 888.5 ;
    END
  END push_block_i[90]
  PIN push_block_i[91]
    DIRECTION INPUT ;
    USE SIGNAL ;
    PORT
      LAYER Metal3 ;
        RECT  0 886.42 0.4 886.82 ;
    END
  END push_block_i[91]
  PIN push_block_i[92]
    DIRECTION INPUT ;
    USE SIGNAL ;
    PORT
      LAYER Metal3 ;
        RECT  0 884.74 0.4 885.14 ;
    END
  END push_block_i[92]
  PIN push_block_i[93]
    DIRECTION INPUT ;
    USE SIGNAL ;
    PORT
      LAYER Metal3 ;
        RECT  0 883.06 0.4 883.46 ;
    END
  END push_block_i[93]
  PIN push_block_i[94]
    DIRECTION INPUT ;
    USE SIGNAL ;
    PORT
      LAYER Metal3 ;
        RECT  0 881.38 0.4 881.78 ;
    END
  END push_block_i[94]
  PIN push_block_i[95]
    DIRECTION INPUT ;
    USE SIGNAL ;
    PORT
      LAYER Metal3 ;
        RECT  0 879.7 0.4 880.1 ;
    END
  END push_block_i[95]
  PIN push_block_i[96]
    DIRECTION INPUT ;
    USE SIGNAL ;
    PORT
      LAYER Metal3 ;
        RECT  0 878.02 0.4 878.42 ;
    END
  END push_block_i[96]
  PIN push_block_i[97]
    DIRECTION INPUT ;
    USE SIGNAL ;
    PORT
      LAYER Metal3 ;
        RECT  0 876.34 0.4 876.74 ;
    END
  END push_block_i[97]
  PIN push_block_i[98]
    DIRECTION INPUT ;
    USE SIGNAL ;
    PORT
      LAYER Metal3 ;
        RECT  0 874.66 0.4 875.06 ;
    END
  END push_block_i[98]
  PIN push_block_i[99]
    DIRECTION INPUT ;
    USE SIGNAL ;
    PORT
      LAYER Metal3 ;
        RECT  0 872.98 0.4 873.38 ;
    END
  END push_block_i[99]
  PIN push_block_i[9]
    DIRECTION INPUT ;
    USE SIGNAL ;
    PORT
      LAYER Metal3 ;
        RECT  0 1024.18 0.4 1024.58 ;
    END
  END push_block_i[9]
  PIN push_count_i[0]
    DIRECTION INPUT ;
    USE SIGNAL ;
    PORT
      LAYER Metal3 ;
        RECT  0 1046.02 0.4 1046.42 ;
    END
  END push_count_i[0]
  PIN push_count_i[1]
    DIRECTION INPUT ;
    USE SIGNAL ;
    PORT
      LAYER Metal3 ;
        RECT  0 1044.34 0.4 1044.74 ;
    END
  END push_count_i[1]
  PIN push_count_i[2]
    DIRECTION INPUT ;
    USE SIGNAL ;
    PORT
      LAYER Metal3 ;
        RECT  0 1042.66 0.4 1043.06 ;
    END
  END push_count_i[2]
  PIN push_count_i[3]
    DIRECTION INPUT ;
    USE SIGNAL ;
    PORT
      LAYER Metal3 ;
        RECT  0 1040.98 0.4 1041.38 ;
    END
  END push_count_i[3]
  PIN push_ready_o
    DIRECTION OUTPUT ;
    USE SIGNAL ;
    PORT
      LAYER Metal3 ;
        RECT  0 1049.38 0.4 1049.78 ;
    END
  END push_ready_o
  PIN push_valid_i
    DIRECTION INPUT ;
    USE SIGNAL ;
    PORT
      LAYER Metal3 ;
        RECT  0 1047.7 0.4 1048.1 ;
    END
  END push_valid_i
  PIN reset_i
    DIRECTION INPUT ;
    USE SIGNAL ;
    PORT
      LAYER Metal2 ;
        RECT  99.16 1099.6 99.56 1100 ;
    END
  END reset_i
  PIN VPWR
    DIRECTION INOUT ;
    USE POWER ;
    PORT
      LAYER TopMetal1 ;
        RECT  5.76 1074.12 793.92 1076.12 ;
        RECT  5.76 1024.12 793.92 1026.12 ;
        RECT  5.76 974.12 793.92 976.12 ;
        RECT  5.76 924.12 793.92 926.12 ;
        RECT  5.76 874.12 793.92 876.12 ;
        RECT  5.76 824.12 793.92 826.12 ;
        RECT  5.76 774.12 793.92 776.12 ;
        RECT  5.76 724.12 793.92 726.12 ;
        RECT  5.76 674.12 793.92 676.12 ;
        RECT  5.76 624.12 793.92 626.12 ;
        RECT  5.76 574.12 793.92 576.12 ;
        RECT  5.76 524.12 793.92 526.12 ;
        RECT  5.76 474.12 793.92 476.12 ;
        RECT  5.76 424.12 793.92 426.12 ;
        RECT  5.76 374.12 793.92 376.12 ;
        RECT  5.76 324.12 793.92 326.12 ;
        RECT  5.76 274.12 793.92 276.12 ;
        RECT  5.76 224.12 793.92 226.12 ;
        RECT  5.76 174.12 793.92 176.12 ;
        RECT  5.76 124.12 793.92 126.12 ;
        RECT  5.76 74.12 793.92 76.12 ;
        RECT  5.76 24.12 793.92 26.12 ;
      LAYER Metal4 ;
        RECT  765.26 14.9 766.26 1085.08 ;
        RECT  715.26 14.9 716.26 1085.08 ;
        RECT  665.26 14.9 666.26 1085.08 ;
        RECT  615.26 14.9 616.26 1085.08 ;
        RECT  565.26 14.9 566.26 1085.08 ;
        RECT  515.26 14.9 516.26 1085.08 ;
        RECT  465.26 14.9 466.26 1085.08 ;
        RECT  415.26 14.9 416.26 1085.08 ;
        RECT  365.26 14.9 366.26 1085.08 ;
        RECT  315.26 14.9 316.26 1085.08 ;
        RECT  265.26 14.9 266.26 1085.08 ;
        RECT  215.26 14.9 216.26 1085.08 ;
        RECT  165.26 14.9 166.26 1085.08 ;
        RECT  115.26 14.9 116.26 1085.08 ;
        RECT  65.26 14.9 66.26 1085.08 ;
        RECT  15.26 14.9 16.26 1085.08 ;
    END
  END VPWR
  PIN VGND
    DIRECTION INOUT ;
    USE GROUND ;
    PORT
      LAYER TopMetal1 ;
        RECT  5.76 1080.12 793.92 1082.12 ;
        RECT  5.76 1030.12 793.92 1032.12 ;
        RECT  5.76 980.12 793.92 982.12 ;
        RECT  5.76 930.12 793.92 932.12 ;
        RECT  5.76 880.12 793.92 882.12 ;
        RECT  5.76 830.12 793.92 832.12 ;
        RECT  5.76 780.12 793.92 782.12 ;
        RECT  5.76 730.12 793.92 732.12 ;
        RECT  5.76 680.12 793.92 682.12 ;
        RECT  5.76 630.12 793.92 632.12 ;
        RECT  5.76 580.12 793.92 582.12 ;
        RECT  5.76 530.12 793.92 532.12 ;
        RECT  5.76 480.12 793.92 482.12 ;
        RECT  5.76 430.12 793.92 432.12 ;
        RECT  5.76 380.12 793.92 382.12 ;
        RECT  5.76 330.12 793.92 332.12 ;
        RECT  5.76 280.12 793.92 282.12 ;
        RECT  5.76 230.12 793.92 232.12 ;
        RECT  5.76 180.12 793.92 182.12 ;
        RECT  5.76 130.12 793.92 132.12 ;
        RECT  5.76 80.12 793.92 82.12 ;
        RECT  5.76 30.12 793.92 32.12 ;
      LAYER Metal4 ;
        RECT  768.26 14.9 769.26 1085.08 ;
        RECT  718.26 14.9 719.26 1085.08 ;
        RECT  668.26 14.9 669.26 1085.08 ;
        RECT  618.26 14.9 619.26 1085.08 ;
        RECT  568.26 14.9 569.26 1085.08 ;
        RECT  518.26 14.9 519.26 1085.08 ;
        RECT  468.26 14.9 469.26 1085.08 ;
        RECT  418.26 14.9 419.26 1085.08 ;
        RECT  368.26 14.9 369.26 1085.08 ;
        RECT  318.26 14.9 319.26 1085.08 ;
        RECT  268.26 14.9 269.26 1085.08 ;
        RECT  218.26 14.9 219.26 1085.08 ;
        RECT  168.26 14.9 169.26 1085.08 ;
        RECT  118.26 14.9 119.26 1085.08 ;
        RECT  68.26 14.9 69.26 1085.08 ;
        RECT  18.26 14.9 19.26 1085.08 ;
    END
  END VGND
  OBS
    LAYER Metal1 ;
     RECT  0 14.9 800 1100 ;
    LAYER Metal2 ;
     RECT  0 14.9 800 1100 ;
    LAYER Metal3 ;
     RECT  0 14.9 800 1100 ;
    LAYER Metal4 ;
     RECT  0 14.9 800 1100 ;
    LAYER TopMetal1 ;
     RECT  0 14.9 800 1100 ;
  END
END ino_decode_queue
END LIBRARY
